# Generated deterministically by seda-macro-lef-normalizer-v1; recipe orfs-ng45-fakeram-metal3-coupledl2-pg-v1.
VERSION 5.8 ;
BUSBITCHARS "[]" ;
DIVIDERCHAR "/" ;

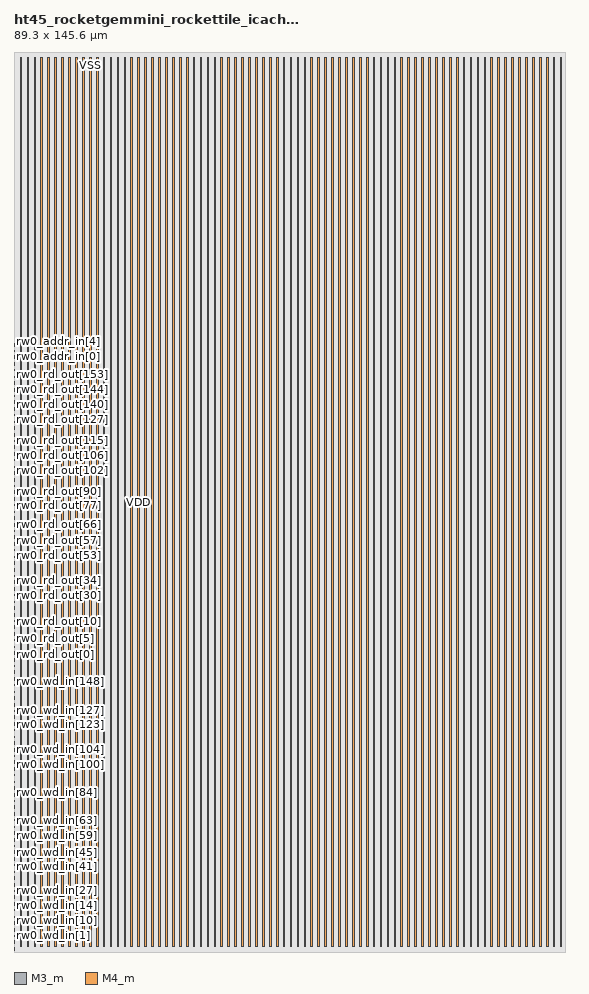
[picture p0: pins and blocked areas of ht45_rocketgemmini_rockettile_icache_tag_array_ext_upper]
MACRO ht45_rocketgemmini_rockettile_icache_tag_array_ext_upper
  FOREIGN ht45_rocketgemmini_rockettile_icache_tag_array_ext_upper 0 0 ;
  CLASS BLOCK ;
  ORIGIN 0 0 ;
  SIZE 89.3 BY 145.6 ;
  SYMMETRY X Y R90 ;
  PIN rw0_wmask_in[0]
    DIRECTION INPUT ;
    USE SIGNAL ;
    SHAPE ABUTMENT ;
    PORT
      LAYER M3_m ;
      RECT 0 0.035 0.07 0.105 ;
    END
  END rw0_wmask_in[0]
  PIN rw0_wmask_in[1]
    DIRECTION INPUT ;
    USE SIGNAL ;
    SHAPE ABUTMENT ;
    PORT
      LAYER M3_m ;
      RECT 0 0.315 0.07 0.385 ;
    END
  END rw0_wmask_in[1]
  PIN rw0_wmask_in[2]
    DIRECTION INPUT ;
    USE SIGNAL ;
    SHAPE ABUTMENT ;
    PORT
      LAYER M3_m ;
      RECT 0 0.595 0.07 0.665 ;
    END
  END rw0_wmask_in[2]
  PIN rw0_wmask_in[3]
    DIRECTION INPUT ;
    USE SIGNAL ;
    SHAPE ABUTMENT ;
    PORT
      LAYER M3_m ;
      RECT 0 0.875 0.07 0.945 ;
    END
  END rw0_wmask_in[3]
  PIN rw0_wmask_in[4]
    DIRECTION INPUT ;
    USE SIGNAL ;
    SHAPE ABUTMENT ;
    PORT
      LAYER M3_m ;
      RECT 0 1.155 0.07 1.225 ;
    END
  END rw0_wmask_in[4]
  PIN rw0_wmask_in[5]
    DIRECTION INPUT ;
    USE SIGNAL ;
    SHAPE ABUTMENT ;
    PORT
      LAYER M3_m ;
      RECT 0 1.435 0.07 1.505 ;
    END
  END rw0_wmask_in[5]
  PIN rw0_wmask_in[6]
    DIRECTION INPUT ;
    USE SIGNAL ;
    SHAPE ABUTMENT ;
    PORT
      LAYER M3_m ;
      RECT 0 1.715 0.07 1.785 ;
    END
  END rw0_wmask_in[6]
  PIN rw0_wmask_in[7]
    DIRECTION INPUT ;
    USE SIGNAL ;
    SHAPE ABUTMENT ;
    PORT
      LAYER M3_m ;
      RECT 0 1.995 0.07 2.065 ;
    END
  END rw0_wmask_in[7]
  PIN rw0_wd_in[0]
    DIRECTION INPUT ;
    USE SIGNAL ;
    SHAPE ABUTMENT ;
    PORT
      LAYER M3_m ;
      RECT 0 2.275 0.07 2.345 ;
    END
  END rw0_wd_in[0]
  PIN rw0_wd_in[1]
    DIRECTION INPUT ;
    USE SIGNAL ;
    SHAPE ABUTMENT ;
    PORT
      LAYER M3_m ;
      RECT 0 2.555 0.07 2.625 ;
    END
  END rw0_wd_in[1]
  PIN rw0_wd_in[2]
    DIRECTION INPUT ;
    USE SIGNAL ;
    SHAPE ABUTMENT ;
    PORT
      LAYER M3_m ;
      RECT 0 2.835 0.07 2.905 ;
    END
  END rw0_wd_in[2]
  PIN rw0_wd_in[3]
    DIRECTION INPUT ;
    USE SIGNAL ;
    SHAPE ABUTMENT ;
    PORT
      LAYER M3_m ;
      RECT 0 3.115 0.07 3.185 ;
    END
  END rw0_wd_in[3]
  PIN rw0_wd_in[4]
    DIRECTION INPUT ;
    USE SIGNAL ;
    SHAPE ABUTMENT ;
    PORT
      LAYER M3_m ;
      RECT 0 3.395 0.07 3.465 ;
    END
  END rw0_wd_in[4]
  PIN rw0_wd_in[5]
    DIRECTION INPUT ;
    USE SIGNAL ;
    SHAPE ABUTMENT ;
    PORT
      LAYER M3_m ;
      RECT 0 3.675 0.07 3.745 ;
    END
  END rw0_wd_in[5]
  PIN rw0_wd_in[6]
    DIRECTION INPUT ;
    USE SIGNAL ;
    SHAPE ABUTMENT ;
    PORT
      LAYER M3_m ;
      RECT 0 3.955 0.07 4.025 ;
    END
  END rw0_wd_in[6]
  PIN rw0_wd_in[7]
    DIRECTION INPUT ;
    USE SIGNAL ;
    SHAPE ABUTMENT ;
    PORT
      LAYER M3_m ;
      RECT 0 4.235 0.07 4.305 ;
    END
  END rw0_wd_in[7]
  PIN rw0_wd_in[8]
    DIRECTION INPUT ;
    USE SIGNAL ;
    SHAPE ABUTMENT ;
    PORT
      LAYER M3_m ;
      RECT 0 4.515 0.07 4.585 ;
    END
  END rw0_wd_in[8]
  PIN rw0_wd_in[9]
    DIRECTION INPUT ;
    USE SIGNAL ;
    SHAPE ABUTMENT ;
    PORT
      LAYER M3_m ;
      RECT 0 4.795 0.07 4.865 ;
    END
  END rw0_wd_in[9]
  PIN rw0_wd_in[10]
    DIRECTION INPUT ;
    USE SIGNAL ;
    SHAPE ABUTMENT ;
    PORT
      LAYER M3_m ;
      RECT 0 5.075 0.07 5.145 ;
    END
  END rw0_wd_in[10]
  PIN rw0_wd_in[11]
    DIRECTION INPUT ;
    USE SIGNAL ;
    SHAPE ABUTMENT ;
    PORT
      LAYER M3_m ;
      RECT 0 5.355 0.07 5.425 ;
    END
  END rw0_wd_in[11]
  PIN rw0_wd_in[12]
    DIRECTION INPUT ;
    USE SIGNAL ;
    SHAPE ABUTMENT ;
    PORT
      LAYER M3_m ;
      RECT 0 5.635 0.07 5.705 ;
    END
  END rw0_wd_in[12]
  PIN rw0_wd_in[13]
    DIRECTION INPUT ;
    USE SIGNAL ;
    SHAPE ABUTMENT ;
    PORT
      LAYER M3_m ;
      RECT 0 5.915 0.07 5.985 ;
    END
  END rw0_wd_in[13]
  PIN rw0_wd_in[14]
    DIRECTION INPUT ;
    USE SIGNAL ;
    SHAPE ABUTMENT ;
    PORT
      LAYER M3_m ;
      RECT 0 6.195 0.07 6.265 ;
    END
  END rw0_wd_in[14]
  PIN rw0_wd_in[15]
    DIRECTION INPUT ;
    USE SIGNAL ;
    SHAPE ABUTMENT ;
    PORT
      LAYER M3_m ;
      RECT 0 6.475 0.07 6.545 ;
    END
  END rw0_wd_in[15]
  PIN rw0_wd_in[16]
    DIRECTION INPUT ;
    USE SIGNAL ;
    SHAPE ABUTMENT ;
    PORT
      LAYER M3_m ;
      RECT 0 6.755 0.07 6.825 ;
    END
  END rw0_wd_in[16]
  PIN rw0_wd_in[17]
    DIRECTION INPUT ;
    USE SIGNAL ;
    SHAPE ABUTMENT ;
    PORT
      LAYER M3_m ;
      RECT 0 7.035 0.07 7.105 ;
    END
  END rw0_wd_in[17]
  PIN rw0_wd_in[18]
    DIRECTION INPUT ;
    USE SIGNAL ;
    SHAPE ABUTMENT ;
    PORT
      LAYER M3_m ;
      RECT 0 7.315 0.07 7.385 ;
    END
  END rw0_wd_in[18]
  PIN rw0_wd_in[19]
    DIRECTION INPUT ;
    USE SIGNAL ;
    SHAPE ABUTMENT ;
    PORT
      LAYER M3_m ;
      RECT 0 7.595 0.07 7.665 ;
    END
  END rw0_wd_in[19]
  PIN rw0_wd_in[20]
    DIRECTION INPUT ;
    USE SIGNAL ;
    SHAPE ABUTMENT ;
    PORT
      LAYER M3_m ;
      RECT 0 7.875 0.07 7.945 ;
    END
  END rw0_wd_in[20]
  PIN rw0_wd_in[21]
    DIRECTION INPUT ;
    USE SIGNAL ;
    SHAPE ABUTMENT ;
    PORT
      LAYER M3_m ;
      RECT 0 8.155 0.07 8.225 ;
    END
  END rw0_wd_in[21]
  PIN rw0_wd_in[22]
    DIRECTION INPUT ;
    USE SIGNAL ;
    SHAPE ABUTMENT ;
    PORT
      LAYER M3_m ;
      RECT 0 8.435 0.07 8.505 ;
    END
  END rw0_wd_in[22]
  PIN rw0_wd_in[23]
    DIRECTION INPUT ;
    USE SIGNAL ;
    SHAPE ABUTMENT ;
    PORT
      LAYER M3_m ;
      RECT 0 8.715 0.07 8.785 ;
    END
  END rw0_wd_in[23]
  PIN rw0_wd_in[24]
    DIRECTION INPUT ;
    USE SIGNAL ;
    SHAPE ABUTMENT ;
    PORT
      LAYER M3_m ;
      RECT 0 8.995 0.07 9.065 ;
    END
  END rw0_wd_in[24]
  PIN rw0_wd_in[25]
    DIRECTION INPUT ;
    USE SIGNAL ;
    SHAPE ABUTMENT ;
    PORT
      LAYER M3_m ;
      RECT 0 9.275 0.07 9.345 ;
    END
  END rw0_wd_in[25]
  PIN rw0_wd_in[26]
    DIRECTION INPUT ;
    USE SIGNAL ;
    SHAPE ABUTMENT ;
    PORT
      LAYER M3_m ;
      RECT 0 9.555 0.07 9.625 ;
    END
  END rw0_wd_in[26]
  PIN rw0_wd_in[27]
    DIRECTION INPUT ;
    USE SIGNAL ;
    SHAPE ABUTMENT ;
    PORT
      LAYER M3_m ;
      RECT 0 9.835 0.07 9.905 ;
    END
  END rw0_wd_in[27]
  PIN rw0_wd_in[28]
    DIRECTION INPUT ;
    USE SIGNAL ;
    SHAPE ABUTMENT ;
    PORT
      LAYER M3_m ;
      RECT 0 10.115 0.07 10.185 ;
    END
  END rw0_wd_in[28]
  PIN rw0_wd_in[29]
    DIRECTION INPUT ;
    USE SIGNAL ;
    SHAPE ABUTMENT ;
    PORT
      LAYER M3_m ;
      RECT 0 10.395 0.07 10.465 ;
    END
  END rw0_wd_in[29]
  PIN rw0_wd_in[30]
    DIRECTION INPUT ;
    USE SIGNAL ;
    SHAPE ABUTMENT ;
    PORT
      LAYER M3_m ;
      RECT 0 10.675 0.07 10.745 ;
    END
  END rw0_wd_in[30]
  PIN rw0_wd_in[31]
    DIRECTION INPUT ;
    USE SIGNAL ;
    SHAPE ABUTMENT ;
    PORT
      LAYER M3_m ;
      RECT 0 10.955 0.07 11.025 ;
    END
  END rw0_wd_in[31]
  PIN rw0_wd_in[32]
    DIRECTION INPUT ;
    USE SIGNAL ;
    SHAPE ABUTMENT ;
    PORT
      LAYER M3_m ;
      RECT 0 11.235 0.07 11.305 ;
    END
  END rw0_wd_in[32]
  PIN rw0_wd_in[33]
    DIRECTION INPUT ;
    USE SIGNAL ;
    SHAPE ABUTMENT ;
    PORT
      LAYER M3_m ;
      RECT 0 11.515 0.07 11.585 ;
    END
  END rw0_wd_in[33]
  PIN rw0_wd_in[34]
    DIRECTION INPUT ;
    USE SIGNAL ;
    SHAPE ABUTMENT ;
    PORT
      LAYER M3_m ;
      RECT 0 11.795 0.07 11.865 ;
    END
  END rw0_wd_in[34]
  PIN rw0_wd_in[35]
    DIRECTION INPUT ;
    USE SIGNAL ;
    SHAPE ABUTMENT ;
    PORT
      LAYER M3_m ;
      RECT 0 12.075 0.07 12.145 ;
    END
  END rw0_wd_in[35]
  PIN rw0_wd_in[36]
    DIRECTION INPUT ;
    USE SIGNAL ;
    SHAPE ABUTMENT ;
    PORT
      LAYER M3_m ;
      RECT 0 12.355 0.07 12.425 ;
    END
  END rw0_wd_in[36]
  PIN rw0_wd_in[37]
    DIRECTION INPUT ;
    USE SIGNAL ;
    SHAPE ABUTMENT ;
    PORT
      LAYER M3_m ;
      RECT 0 12.635 0.07 12.705 ;
    END
  END rw0_wd_in[37]
  PIN rw0_wd_in[38]
    DIRECTION INPUT ;
    USE SIGNAL ;
    SHAPE ABUTMENT ;
    PORT
      LAYER M3_m ;
      RECT 0 12.915 0.07 12.985 ;
    END
  END rw0_wd_in[38]
  PIN rw0_wd_in[39]
    DIRECTION INPUT ;
    USE SIGNAL ;
    SHAPE ABUTMENT ;
    PORT
      LAYER M3_m ;
      RECT 0 13.195 0.07 13.265 ;
    END
  END rw0_wd_in[39]
  PIN rw0_wd_in[40]
    DIRECTION INPUT ;
    USE SIGNAL ;
    SHAPE ABUTMENT ;
    PORT
      LAYER M3_m ;
      RECT 0 13.475 0.07 13.545 ;
    END
  END rw0_wd_in[40]
  PIN rw0_wd_in[41]
    DIRECTION INPUT ;
    USE SIGNAL ;
    SHAPE ABUTMENT ;
    PORT
      LAYER M3_m ;
      RECT 0 13.755 0.07 13.825 ;
    END
  END rw0_wd_in[41]
  PIN rw0_wd_in[42]
    DIRECTION INPUT ;
    USE SIGNAL ;
    SHAPE ABUTMENT ;
    PORT
      LAYER M3_m ;
      RECT 0 14.035 0.07 14.105 ;
    END
  END rw0_wd_in[42]
  PIN rw0_wd_in[43]
    DIRECTION INPUT ;
    USE SIGNAL ;
    SHAPE ABUTMENT ;
    PORT
      LAYER M3_m ;
      RECT 0 14.315 0.07 14.385 ;
    END
  END rw0_wd_in[43]
  PIN rw0_wd_in[44]
    DIRECTION INPUT ;
    USE SIGNAL ;
    SHAPE ABUTMENT ;
    PORT
      LAYER M3_m ;
      RECT 0 14.595 0.07 14.665 ;
    END
  END rw0_wd_in[44]
  PIN rw0_wd_in[45]
    DIRECTION INPUT ;
    USE SIGNAL ;
    SHAPE ABUTMENT ;
    PORT
      LAYER M3_m ;
      RECT 0 14.875 0.07 14.945 ;
    END
  END rw0_wd_in[45]
  PIN rw0_wd_in[46]
    DIRECTION INPUT ;
    USE SIGNAL ;
    SHAPE ABUTMENT ;
    PORT
      LAYER M3_m ;
      RECT 0 15.155 0.07 15.225 ;
    END
  END rw0_wd_in[46]
  PIN rw0_wd_in[47]
    DIRECTION INPUT ;
    USE SIGNAL ;
    SHAPE ABUTMENT ;
    PORT
      LAYER M3_m ;
      RECT 0 15.435 0.07 15.505 ;
    END
  END rw0_wd_in[47]
  PIN rw0_wd_in[48]
    DIRECTION INPUT ;
    USE SIGNAL ;
    SHAPE ABUTMENT ;
    PORT
      LAYER M3_m ;
      RECT 0 15.715 0.07 15.785 ;
    END
  END rw0_wd_in[48]
  PIN rw0_wd_in[49]
    DIRECTION INPUT ;
    USE SIGNAL ;
    SHAPE ABUTMENT ;
    PORT
      LAYER M3_m ;
      RECT 0 15.995 0.07 16.065 ;
    END
  END rw0_wd_in[49]
  PIN rw0_wd_in[50]
    DIRECTION INPUT ;
    USE SIGNAL ;
    SHAPE ABUTMENT ;
    PORT
      LAYER M3_m ;
      RECT 0 16.275 0.07 16.345 ;
    END
  END rw0_wd_in[50]
  PIN rw0_wd_in[51]
    DIRECTION INPUT ;
    USE SIGNAL ;
    SHAPE ABUTMENT ;
    PORT
      LAYER M3_m ;
      RECT 0 16.555 0.07 16.625 ;
    END
  END rw0_wd_in[51]
  PIN rw0_wd_in[52]
    DIRECTION INPUT ;
    USE SIGNAL ;
    SHAPE ABUTMENT ;
    PORT
      LAYER M3_m ;
      RECT 0 16.835 0.07 16.905 ;
    END
  END rw0_wd_in[52]
  PIN rw0_wd_in[53]
    DIRECTION INPUT ;
    USE SIGNAL ;
    SHAPE ABUTMENT ;
    PORT
      LAYER M3_m ;
      RECT 0 17.115 0.07 17.185 ;
    END
  END rw0_wd_in[53]
  PIN rw0_wd_in[54]
    DIRECTION INPUT ;
    USE SIGNAL ;
    SHAPE ABUTMENT ;
    PORT
      LAYER M3_m ;
      RECT 0 17.395 0.07 17.465 ;
    END
  END rw0_wd_in[54]
  PIN rw0_wd_in[55]
    DIRECTION INPUT ;
    USE SIGNAL ;
    SHAPE ABUTMENT ;
    PORT
      LAYER M3_m ;
      RECT 0 17.675 0.07 17.745 ;
    END
  END rw0_wd_in[55]
  PIN rw0_wd_in[56]
    DIRECTION INPUT ;
    USE SIGNAL ;
    SHAPE ABUTMENT ;
    PORT
      LAYER M3_m ;
      RECT 0 17.955 0.07 18.025 ;
    END
  END rw0_wd_in[56]
  PIN rw0_wd_in[57]
    DIRECTION INPUT ;
    USE SIGNAL ;
    SHAPE ABUTMENT ;
    PORT
      LAYER M3_m ;
      RECT 0 18.235 0.07 18.305 ;
    END
  END rw0_wd_in[57]
  PIN rw0_wd_in[58]
    DIRECTION INPUT ;
    USE SIGNAL ;
    SHAPE ABUTMENT ;
    PORT
      LAYER M3_m ;
      RECT 0 18.515 0.07 18.585 ;
    END
  END rw0_wd_in[58]
  PIN rw0_wd_in[59]
    DIRECTION INPUT ;
    USE SIGNAL ;
    SHAPE ABUTMENT ;
    PORT
      LAYER M3_m ;
      RECT 0 18.795 0.07 18.865 ;
    END
  END rw0_wd_in[59]
  PIN rw0_wd_in[60]
    DIRECTION INPUT ;
    USE SIGNAL ;
    SHAPE ABUTMENT ;
    PORT
      LAYER M3_m ;
      RECT 0 19.075 0.07 19.145 ;
    END
  END rw0_wd_in[60]
  PIN rw0_wd_in[61]
    DIRECTION INPUT ;
    USE SIGNAL ;
    SHAPE ABUTMENT ;
    PORT
      LAYER M3_m ;
      RECT 0 19.355 0.07 19.425 ;
    END
  END rw0_wd_in[61]
  PIN rw0_wd_in[62]
    DIRECTION INPUT ;
    USE SIGNAL ;
    SHAPE ABUTMENT ;
    PORT
      LAYER M3_m ;
      RECT 0 19.635 0.07 19.705 ;
    END
  END rw0_wd_in[62]
  PIN rw0_wd_in[63]
    DIRECTION INPUT ;
    USE SIGNAL ;
    SHAPE ABUTMENT ;
    PORT
      LAYER M3_m ;
      RECT 0 19.915 0.07 19.985 ;
    END
  END rw0_wd_in[63]
  PIN rw0_wd_in[64]
    DIRECTION INPUT ;
    USE SIGNAL ;
    SHAPE ABUTMENT ;
    PORT
      LAYER M3_m ;
      RECT 0 20.195 0.07 20.265 ;
    END
  END rw0_wd_in[64]
  PIN rw0_wd_in[65]
    DIRECTION INPUT ;
    USE SIGNAL ;
    SHAPE ABUTMENT ;
    PORT
      LAYER M3_m ;
      RECT 0 20.475 0.07 20.545 ;
    END
  END rw0_wd_in[65]
  PIN rw0_wd_in[66]
    DIRECTION INPUT ;
    USE SIGNAL ;
    SHAPE ABUTMENT ;
    PORT
      LAYER M3_m ;
      RECT 0 20.755 0.07 20.825 ;
    END
  END rw0_wd_in[66]
  PIN rw0_wd_in[67]
    DIRECTION INPUT ;
    USE SIGNAL ;
    SHAPE ABUTMENT ;
    PORT
      LAYER M3_m ;
      RECT 0 21.035 0.07 21.105 ;
    END
  END rw0_wd_in[67]
  PIN rw0_wd_in[68]
    DIRECTION INPUT ;
    USE SIGNAL ;
    SHAPE ABUTMENT ;
    PORT
      LAYER M3_m ;
      RECT 0 21.315 0.07 21.385 ;
    END
  END rw0_wd_in[68]
  PIN rw0_wd_in[69]
    DIRECTION INPUT ;
    USE SIGNAL ;
    SHAPE ABUTMENT ;
    PORT
      LAYER M3_m ;
      RECT 0 21.595 0.07 21.665 ;
    END
  END rw0_wd_in[69]
  PIN rw0_wd_in[70]
    DIRECTION INPUT ;
    USE SIGNAL ;
    SHAPE ABUTMENT ;
    PORT
      LAYER M3_m ;
      RECT 0 21.875 0.07 21.945 ;
    END
  END rw0_wd_in[70]
  PIN rw0_wd_in[71]
    DIRECTION INPUT ;
    USE SIGNAL ;
    SHAPE ABUTMENT ;
    PORT
      LAYER M3_m ;
      RECT 0 22.155 0.07 22.225 ;
    END
  END rw0_wd_in[71]
  PIN rw0_wd_in[72]
    DIRECTION INPUT ;
    USE SIGNAL ;
    SHAPE ABUTMENT ;
    PORT
      LAYER M3_m ;
      RECT 0 22.435 0.07 22.505 ;
    END
  END rw0_wd_in[72]
  PIN rw0_wd_in[73]
    DIRECTION INPUT ;
    USE SIGNAL ;
    SHAPE ABUTMENT ;
    PORT
      LAYER M3_m ;
      RECT 0 22.715 0.07 22.785 ;
    END
  END rw0_wd_in[73]
  PIN rw0_wd_in[74]
    DIRECTION INPUT ;
    USE SIGNAL ;
    SHAPE ABUTMENT ;
    PORT
      LAYER M3_m ;
      RECT 0 22.995 0.07 23.065 ;
    END
  END rw0_wd_in[74]
  PIN rw0_wd_in[75]
    DIRECTION INPUT ;
    USE SIGNAL ;
    SHAPE ABUTMENT ;
    PORT
      LAYER M3_m ;
      RECT 0 23.275 0.07 23.345 ;
    END
  END rw0_wd_in[75]
  PIN rw0_wd_in[76]
    DIRECTION INPUT ;
    USE SIGNAL ;
    SHAPE ABUTMENT ;
    PORT
      LAYER M3_m ;
      RECT 0 23.555 0.07 23.625 ;
    END
  END rw0_wd_in[76]
  PIN rw0_wd_in[77]
    DIRECTION INPUT ;
    USE SIGNAL ;
    SHAPE ABUTMENT ;
    PORT
      LAYER M3_m ;
      RECT 0 23.835 0.07 23.905 ;
    END
  END rw0_wd_in[77]
  PIN rw0_wd_in[78]
    DIRECTION INPUT ;
    USE SIGNAL ;
    SHAPE ABUTMENT ;
    PORT
      LAYER M3_m ;
      RECT 0 24.115 0.07 24.185 ;
    END
  END rw0_wd_in[78]
  PIN rw0_wd_in[79]
    DIRECTION INPUT ;
    USE SIGNAL ;
    SHAPE ABUTMENT ;
    PORT
      LAYER M3_m ;
      RECT 0 24.395 0.07 24.465 ;
    END
  END rw0_wd_in[79]
  PIN rw0_wd_in[80]
    DIRECTION INPUT ;
    USE SIGNAL ;
    SHAPE ABUTMENT ;
    PORT
      LAYER M3_m ;
      RECT 0 24.675 0.07 24.745 ;
    END
  END rw0_wd_in[80]
  PIN rw0_wd_in[81]
    DIRECTION INPUT ;
    USE SIGNAL ;
    SHAPE ABUTMENT ;
    PORT
      LAYER M3_m ;
      RECT 0 24.955 0.07 25.025 ;
    END
  END rw0_wd_in[81]
  PIN rw0_wd_in[82]
    DIRECTION INPUT ;
    USE SIGNAL ;
    SHAPE ABUTMENT ;
    PORT
      LAYER M3_m ;
      RECT 0 25.235 0.07 25.305 ;
    END
  END rw0_wd_in[82]
  PIN rw0_wd_in[83]
    DIRECTION INPUT ;
    USE SIGNAL ;
    SHAPE ABUTMENT ;
    PORT
      LAYER M3_m ;
      RECT 0 25.515 0.07 25.585 ;
    END
  END rw0_wd_in[83]
  PIN rw0_wd_in[84]
    DIRECTION INPUT ;
    USE SIGNAL ;
    SHAPE ABUTMENT ;
    PORT
      LAYER M3_m ;
      RECT 0 25.795 0.07 25.865 ;
    END
  END rw0_wd_in[84]
  PIN rw0_wd_in[85]
    DIRECTION INPUT ;
    USE SIGNAL ;
    SHAPE ABUTMENT ;
    PORT
      LAYER M3_m ;
      RECT 0 26.075 0.07 26.145 ;
    END
  END rw0_wd_in[85]
  PIN rw0_wd_in[86]
    DIRECTION INPUT ;
    USE SIGNAL ;
    SHAPE ABUTMENT ;
    PORT
      LAYER M3_m ;
      RECT 0 26.355 0.07 26.425 ;
    END
  END rw0_wd_in[86]
  PIN rw0_wd_in[87]
    DIRECTION INPUT ;
    USE SIGNAL ;
    SHAPE ABUTMENT ;
    PORT
      LAYER M3_m ;
      RECT 0 26.635 0.07 26.705 ;
    END
  END rw0_wd_in[87]
  PIN rw0_wd_in[88]
    DIRECTION INPUT ;
    USE SIGNAL ;
    SHAPE ABUTMENT ;
    PORT
      LAYER M3_m ;
      RECT 0 26.915 0.07 26.985 ;
    END
  END rw0_wd_in[88]
  PIN rw0_wd_in[89]
    DIRECTION INPUT ;
    USE SIGNAL ;
    SHAPE ABUTMENT ;
    PORT
      LAYER M3_m ;
      RECT 0 27.195 0.07 27.265 ;
    END
  END rw0_wd_in[89]
  PIN rw0_wd_in[90]
    DIRECTION INPUT ;
    USE SIGNAL ;
    SHAPE ABUTMENT ;
    PORT
      LAYER M3_m ;
      RECT 0 27.475 0.07 27.545 ;
    END
  END rw0_wd_in[90]
  PIN rw0_wd_in[91]
    DIRECTION INPUT ;
    USE SIGNAL ;
    SHAPE ABUTMENT ;
    PORT
      LAYER M3_m ;
      RECT 0 27.755 0.07 27.825 ;
    END
  END rw0_wd_in[91]
  PIN rw0_wd_in[92]
    DIRECTION INPUT ;
    USE SIGNAL ;
    SHAPE ABUTMENT ;
    PORT
      LAYER M3_m ;
      RECT 0 28.035 0.07 28.105 ;
    END
  END rw0_wd_in[92]
  PIN rw0_wd_in[93]
    DIRECTION INPUT ;
    USE SIGNAL ;
    SHAPE ABUTMENT ;
    PORT
      LAYER M3_m ;
      RECT 0 28.315 0.07 28.385 ;
    END
  END rw0_wd_in[93]
  PIN rw0_wd_in[94]
    DIRECTION INPUT ;
    USE SIGNAL ;
    SHAPE ABUTMENT ;
    PORT
      LAYER M3_m ;
      RECT 0 28.595 0.07 28.665 ;
    END
  END rw0_wd_in[94]
  PIN rw0_wd_in[95]
    DIRECTION INPUT ;
    USE SIGNAL ;
    SHAPE ABUTMENT ;
    PORT
      LAYER M3_m ;
      RECT 0 28.875 0.07 28.945 ;
    END
  END rw0_wd_in[95]
  PIN rw0_wd_in[96]
    DIRECTION INPUT ;
    USE SIGNAL ;
    SHAPE ABUTMENT ;
    PORT
      LAYER M3_m ;
      RECT 0 29.155 0.07 29.225 ;
    END
  END rw0_wd_in[96]
  PIN rw0_wd_in[97]
    DIRECTION INPUT ;
    USE SIGNAL ;
    SHAPE ABUTMENT ;
    PORT
      LAYER M3_m ;
      RECT 0 29.435 0.07 29.505 ;
    END
  END rw0_wd_in[97]
  PIN rw0_wd_in[98]
    DIRECTION INPUT ;
    USE SIGNAL ;
    SHAPE ABUTMENT ;
    PORT
      LAYER M3_m ;
      RECT 0 29.715 0.07 29.785 ;
    END
  END rw0_wd_in[98]
  PIN rw0_wd_in[99]
    DIRECTION INPUT ;
    USE SIGNAL ;
    SHAPE ABUTMENT ;
    PORT
      LAYER M3_m ;
      RECT 0 29.995 0.07 30.065 ;
    END
  END rw0_wd_in[99]
  PIN rw0_wd_in[100]
    DIRECTION INPUT ;
    USE SIGNAL ;
    SHAPE ABUTMENT ;
    PORT
      LAYER M3_m ;
      RECT 0 30.275 0.07 30.345 ;
    END
  END rw0_wd_in[100]
  PIN rw0_wd_in[101]
    DIRECTION INPUT ;
    USE SIGNAL ;
    SHAPE ABUTMENT ;
    PORT
      LAYER M3_m ;
      RECT 0 30.555 0.07 30.625 ;
    END
  END rw0_wd_in[101]
  PIN rw0_wd_in[102]
    DIRECTION INPUT ;
    USE SIGNAL ;
    SHAPE ABUTMENT ;
    PORT
      LAYER M3_m ;
      RECT 0 30.835 0.07 30.905 ;
    END
  END rw0_wd_in[102]
  PIN rw0_wd_in[103]
    DIRECTION INPUT ;
    USE SIGNAL ;
    SHAPE ABUTMENT ;
    PORT
      LAYER M3_m ;
      RECT 0 31.115 0.07 31.185 ;
    END
  END rw0_wd_in[103]
  PIN rw0_wd_in[104]
    DIRECTION INPUT ;
    USE SIGNAL ;
    SHAPE ABUTMENT ;
    PORT
      LAYER M3_m ;
      RECT 0 31.395 0.07 31.465 ;
    END
  END rw0_wd_in[104]
  PIN rw0_wd_in[105]
    DIRECTION INPUT ;
    USE SIGNAL ;
    SHAPE ABUTMENT ;
    PORT
      LAYER M3_m ;
      RECT 0 31.675 0.07 31.745 ;
    END
  END rw0_wd_in[105]
  PIN rw0_wd_in[106]
    DIRECTION INPUT ;
    USE SIGNAL ;
    SHAPE ABUTMENT ;
    PORT
      LAYER M3_m ;
      RECT 0 31.955 0.07 32.025 ;
    END
  END rw0_wd_in[106]
  PIN rw0_wd_in[107]
    DIRECTION INPUT ;
    USE SIGNAL ;
    SHAPE ABUTMENT ;
    PORT
      LAYER M3_m ;
      RECT 0 32.235 0.07 32.305 ;
    END
  END rw0_wd_in[107]
  PIN rw0_wd_in[108]
    DIRECTION INPUT ;
    USE SIGNAL ;
    SHAPE ABUTMENT ;
    PORT
      LAYER M3_m ;
      RECT 0 32.515 0.07 32.585 ;
    END
  END rw0_wd_in[108]
  PIN rw0_wd_in[109]
    DIRECTION INPUT ;
    USE SIGNAL ;
    SHAPE ABUTMENT ;
    PORT
      LAYER M3_m ;
      RECT 0 32.795 0.07 32.865 ;
    END
  END rw0_wd_in[109]
  PIN rw0_wd_in[110]
    DIRECTION INPUT ;
    USE SIGNAL ;
    SHAPE ABUTMENT ;
    PORT
      LAYER M3_m ;
      RECT 0 33.075 0.07 33.145 ;
    END
  END rw0_wd_in[110]
  PIN rw0_wd_in[111]
    DIRECTION INPUT ;
    USE SIGNAL ;
    SHAPE ABUTMENT ;
    PORT
      LAYER M3_m ;
      RECT 0 33.355 0.07 33.425 ;
    END
  END rw0_wd_in[111]
  PIN rw0_wd_in[112]
    DIRECTION INPUT ;
    USE SIGNAL ;
    SHAPE ABUTMENT ;
    PORT
      LAYER M3_m ;
      RECT 0 33.635 0.07 33.705 ;
    END
  END rw0_wd_in[112]
  PIN rw0_wd_in[113]
    DIRECTION INPUT ;
    USE SIGNAL ;
    SHAPE ABUTMENT ;
    PORT
      LAYER M3_m ;
      RECT 0 33.915 0.07 33.985 ;
    END
  END rw0_wd_in[113]
  PIN rw0_wd_in[114]
    DIRECTION INPUT ;
    USE SIGNAL ;
    SHAPE ABUTMENT ;
    PORT
      LAYER M3_m ;
      RECT 0 34.195 0.07 34.265 ;
    END
  END rw0_wd_in[114]
  PIN rw0_wd_in[115]
    DIRECTION INPUT ;
    USE SIGNAL ;
    SHAPE ABUTMENT ;
    PORT
      LAYER M3_m ;
      RECT 0 34.475 0.07 34.545 ;
    END
  END rw0_wd_in[115]
  PIN rw0_wd_in[116]
    DIRECTION INPUT ;
    USE SIGNAL ;
    SHAPE ABUTMENT ;
    PORT
      LAYER M3_m ;
      RECT 0 34.755 0.07 34.825 ;
    END
  END rw0_wd_in[116]
  PIN rw0_wd_in[117]
    DIRECTION INPUT ;
    USE SIGNAL ;
    SHAPE ABUTMENT ;
    PORT
      LAYER M3_m ;
      RECT 0 35.035 0.07 35.105 ;
    END
  END rw0_wd_in[117]
  PIN rw0_wd_in[118]
    DIRECTION INPUT ;
    USE SIGNAL ;
    SHAPE ABUTMENT ;
    PORT
      LAYER M3_m ;
      RECT 0 35.315 0.07 35.385 ;
    END
  END rw0_wd_in[118]
  PIN rw0_wd_in[119]
    DIRECTION INPUT ;
    USE SIGNAL ;
    SHAPE ABUTMENT ;
    PORT
      LAYER M3_m ;
      RECT 0 35.595 0.07 35.665 ;
    END
  END rw0_wd_in[119]
  PIN rw0_wd_in[120]
    DIRECTION INPUT ;
    USE SIGNAL ;
    SHAPE ABUTMENT ;
    PORT
      LAYER M3_m ;
      RECT 0 35.875 0.07 35.945 ;
    END
  END rw0_wd_in[120]
  PIN rw0_wd_in[121]
    DIRECTION INPUT ;
    USE SIGNAL ;
    SHAPE ABUTMENT ;
    PORT
      LAYER M3_m ;
      RECT 0 36.155 0.07 36.225 ;
    END
  END rw0_wd_in[121]
  PIN rw0_wd_in[122]
    DIRECTION INPUT ;
    USE SIGNAL ;
    SHAPE ABUTMENT ;
    PORT
      LAYER M3_m ;
      RECT 0 36.435 0.07 36.505 ;
    END
  END rw0_wd_in[122]
  PIN rw0_wd_in[123]
    DIRECTION INPUT ;
    USE SIGNAL ;
    SHAPE ABUTMENT ;
    PORT
      LAYER M3_m ;
      RECT 0 36.715 0.07 36.785 ;
    END
  END rw0_wd_in[123]
  PIN rw0_wd_in[124]
    DIRECTION INPUT ;
    USE SIGNAL ;
    SHAPE ABUTMENT ;
    PORT
      LAYER M3_m ;
      RECT 0 36.995 0.07 37.065 ;
    END
  END rw0_wd_in[124]
  PIN rw0_wd_in[125]
    DIRECTION INPUT ;
    USE SIGNAL ;
    SHAPE ABUTMENT ;
    PORT
      LAYER M3_m ;
      RECT 0 37.275 0.07 37.345 ;
    END
  END rw0_wd_in[125]
  PIN rw0_wd_in[126]
    DIRECTION INPUT ;
    USE SIGNAL ;
    SHAPE ABUTMENT ;
    PORT
      LAYER M3_m ;
      RECT 0 37.555 0.07 37.625 ;
    END
  END rw0_wd_in[126]
  PIN rw0_wd_in[127]
    DIRECTION INPUT ;
    USE SIGNAL ;
    SHAPE ABUTMENT ;
    PORT
      LAYER M3_m ;
      RECT 0 37.835 0.07 37.905 ;
    END
  END rw0_wd_in[127]
  PIN rw0_wd_in[128]
    DIRECTION INPUT ;
    USE SIGNAL ;
    SHAPE ABUTMENT ;
    PORT
      LAYER M3_m ;
      RECT 0 38.115 0.07 38.185 ;
    END
  END rw0_wd_in[128]
  PIN rw0_wd_in[129]
    DIRECTION INPUT ;
    USE SIGNAL ;
    SHAPE ABUTMENT ;
    PORT
      LAYER M3_m ;
      RECT 0 38.395 0.07 38.465 ;
    END
  END rw0_wd_in[129]
  PIN rw0_wd_in[130]
    DIRECTION INPUT ;
    USE SIGNAL ;
    SHAPE ABUTMENT ;
    PORT
      LAYER M3_m ;
      RECT 0 38.675 0.07 38.745 ;
    END
  END rw0_wd_in[130]
  PIN rw0_wd_in[131]
    DIRECTION INPUT ;
    USE SIGNAL ;
    SHAPE ABUTMENT ;
    PORT
      LAYER M3_m ;
      RECT 0 38.955 0.07 39.025 ;
    END
  END rw0_wd_in[131]
  PIN rw0_wd_in[132]
    DIRECTION INPUT ;
    USE SIGNAL ;
    SHAPE ABUTMENT ;
    PORT
      LAYER M3_m ;
      RECT 0 39.235 0.07 39.305 ;
    END
  END rw0_wd_in[132]
  PIN rw0_wd_in[133]
    DIRECTION INPUT ;
    USE SIGNAL ;
    SHAPE ABUTMENT ;
    PORT
      LAYER M3_m ;
      RECT 0 39.515 0.07 39.585 ;
    END
  END rw0_wd_in[133]
  PIN rw0_wd_in[134]
    DIRECTION INPUT ;
    USE SIGNAL ;
    SHAPE ABUTMENT ;
    PORT
      LAYER M3_m ;
      RECT 0 39.795 0.07 39.865 ;
    END
  END rw0_wd_in[134]
  PIN rw0_wd_in[135]
    DIRECTION INPUT ;
    USE SIGNAL ;
    SHAPE ABUTMENT ;
    PORT
      LAYER M3_m ;
      RECT 0 40.075 0.07 40.145 ;
    END
  END rw0_wd_in[135]
  PIN rw0_wd_in[136]
    DIRECTION INPUT ;
    USE SIGNAL ;
    SHAPE ABUTMENT ;
    PORT
      LAYER M3_m ;
      RECT 0 40.355 0.07 40.425 ;
    END
  END rw0_wd_in[136]
  PIN rw0_wd_in[137]
    DIRECTION INPUT ;
    USE SIGNAL ;
    SHAPE ABUTMENT ;
    PORT
      LAYER M3_m ;
      RECT 0 40.635 0.07 40.705 ;
    END
  END rw0_wd_in[137]
  PIN rw0_wd_in[138]
    DIRECTION INPUT ;
    USE SIGNAL ;
    SHAPE ABUTMENT ;
    PORT
      LAYER M3_m ;
      RECT 0 40.915 0.07 40.985 ;
    END
  END rw0_wd_in[138]
  PIN rw0_wd_in[139]
    DIRECTION INPUT ;
    USE SIGNAL ;
    SHAPE ABUTMENT ;
    PORT
      LAYER M3_m ;
      RECT 0 41.195 0.07 41.265 ;
    END
  END rw0_wd_in[139]
  PIN rw0_wd_in[140]
    DIRECTION INPUT ;
    USE SIGNAL ;
    SHAPE ABUTMENT ;
    PORT
      LAYER M3_m ;
      RECT 0 41.475 0.07 41.545 ;
    END
  END rw0_wd_in[140]
  PIN rw0_wd_in[141]
    DIRECTION INPUT ;
    USE SIGNAL ;
    SHAPE ABUTMENT ;
    PORT
      LAYER M3_m ;
      RECT 0 41.755 0.07 41.825 ;
    END
  END rw0_wd_in[141]
  PIN rw0_wd_in[142]
    DIRECTION INPUT ;
    USE SIGNAL ;
    SHAPE ABUTMENT ;
    PORT
      LAYER M3_m ;
      RECT 0 42.035 0.07 42.105 ;
    END
  END rw0_wd_in[142]
  PIN rw0_wd_in[143]
    DIRECTION INPUT ;
    USE SIGNAL ;
    SHAPE ABUTMENT ;
    PORT
      LAYER M3_m ;
      RECT 0 42.315 0.07 42.385 ;
    END
  END rw0_wd_in[143]
  PIN rw0_wd_in[144]
    DIRECTION INPUT ;
    USE SIGNAL ;
    SHAPE ABUTMENT ;
    PORT
      LAYER M3_m ;
      RECT 0 42.595 0.07 42.665 ;
    END
  END rw0_wd_in[144]
  PIN rw0_wd_in[145]
    DIRECTION INPUT ;
    USE SIGNAL ;
    SHAPE ABUTMENT ;
    PORT
      LAYER M3_m ;
      RECT 0 42.875 0.07 42.945 ;
    END
  END rw0_wd_in[145]
  PIN rw0_wd_in[146]
    DIRECTION INPUT ;
    USE SIGNAL ;
    SHAPE ABUTMENT ;
    PORT
      LAYER M3_m ;
      RECT 0 43.155 0.07 43.225 ;
    END
  END rw0_wd_in[146]
  PIN rw0_wd_in[147]
    DIRECTION INPUT ;
    USE SIGNAL ;
    SHAPE ABUTMENT ;
    PORT
      LAYER M3_m ;
      RECT 0 43.435 0.07 43.505 ;
    END
  END rw0_wd_in[147]
  PIN rw0_wd_in[148]
    DIRECTION INPUT ;
    USE SIGNAL ;
    SHAPE ABUTMENT ;
    PORT
      LAYER M3_m ;
      RECT 0 43.715 0.07 43.785 ;
    END
  END rw0_wd_in[148]
  PIN rw0_wd_in[149]
    DIRECTION INPUT ;
    USE SIGNAL ;
    SHAPE ABUTMENT ;
    PORT
      LAYER M3_m ;
      RECT 0 43.995 0.07 44.065 ;
    END
  END rw0_wd_in[149]
  PIN rw0_wd_in[150]
    DIRECTION INPUT ;
    USE SIGNAL ;
    SHAPE ABUTMENT ;
    PORT
      LAYER M3_m ;
      RECT 0 44.275 0.07 44.345 ;
    END
  END rw0_wd_in[150]
  PIN rw0_wd_in[151]
    DIRECTION INPUT ;
    USE SIGNAL ;
    SHAPE ABUTMENT ;
    PORT
      LAYER M3_m ;
      RECT 0 44.555 0.07 44.625 ;
    END
  END rw0_wd_in[151]
  PIN rw0_wd_in[152]
    DIRECTION INPUT ;
    USE SIGNAL ;
    SHAPE ABUTMENT ;
    PORT
      LAYER M3_m ;
      RECT 0 44.835 0.07 44.905 ;
    END
  END rw0_wd_in[152]
  PIN rw0_wd_in[153]
    DIRECTION INPUT ;
    USE SIGNAL ;
    SHAPE ABUTMENT ;
    PORT
      LAYER M3_m ;
      RECT 0 45.115 0.07 45.185 ;
    END
  END rw0_wd_in[153]
  PIN rw0_wd_in[154]
    DIRECTION INPUT ;
    USE SIGNAL ;
    SHAPE ABUTMENT ;
    PORT
      LAYER M3_m ;
      RECT 0 45.395 0.07 45.465 ;
    END
  END rw0_wd_in[154]
  PIN rw0_wd_in[155]
    DIRECTION INPUT ;
    USE SIGNAL ;
    SHAPE ABUTMENT ;
    PORT
      LAYER M3_m ;
      RECT 0 45.675 0.07 45.745 ;
    END
  END rw0_wd_in[155]
  PIN rw0_wd_in[156]
    DIRECTION INPUT ;
    USE SIGNAL ;
    SHAPE ABUTMENT ;
    PORT
      LAYER M3_m ;
      RECT 0 45.955 0.07 46.025 ;
    END
  END rw0_wd_in[156]
  PIN rw0_wd_in[157]
    DIRECTION INPUT ;
    USE SIGNAL ;
    SHAPE ABUTMENT ;
    PORT
      LAYER M3_m ;
      RECT 0 46.235 0.07 46.305 ;
    END
  END rw0_wd_in[157]
  PIN rw0_wd_in[158]
    DIRECTION INPUT ;
    USE SIGNAL ;
    SHAPE ABUTMENT ;
    PORT
      LAYER M3_m ;
      RECT 0 46.515 0.07 46.585 ;
    END
  END rw0_wd_in[158]
  PIN rw0_wd_in[159]
    DIRECTION INPUT ;
    USE SIGNAL ;
    SHAPE ABUTMENT ;
    PORT
      LAYER M3_m ;
      RECT 0 46.795 0.07 46.865 ;
    END
  END rw0_wd_in[159]
  PIN rw0_wd_in[160]
    DIRECTION INPUT ;
    USE SIGNAL ;
    SHAPE ABUTMENT ;
    PORT
      LAYER M3_m ;
      RECT 0 47.075 0.07 47.145 ;
    END
  END rw0_wd_in[160]
  PIN rw0_wd_in[161]
    DIRECTION INPUT ;
    USE SIGNAL ;
    SHAPE ABUTMENT ;
    PORT
      LAYER M3_m ;
      RECT 0 47.355 0.07 47.425 ;
    END
  END rw0_wd_in[161]
  PIN rw0_wd_in[162]
    DIRECTION INPUT ;
    USE SIGNAL ;
    SHAPE ABUTMENT ;
    PORT
      LAYER M3_m ;
      RECT 0 47.635 0.07 47.705 ;
    END
  END rw0_wd_in[162]
  PIN rw0_wd_in[163]
    DIRECTION INPUT ;
    USE SIGNAL ;
    SHAPE ABUTMENT ;
    PORT
      LAYER M3_m ;
      RECT 0 47.915 0.07 47.985 ;
    END
  END rw0_wd_in[163]
  PIN rw0_wd_in[164]
    DIRECTION INPUT ;
    USE SIGNAL ;
    SHAPE ABUTMENT ;
    PORT
      LAYER M3_m ;
      RECT 0 48.195 0.07 48.265 ;
    END
  END rw0_wd_in[164]
  PIN rw0_wd_in[165]
    DIRECTION INPUT ;
    USE SIGNAL ;
    SHAPE ABUTMENT ;
    PORT
      LAYER M3_m ;
      RECT 0 48.475 0.07 48.545 ;
    END
  END rw0_wd_in[165]
  PIN rw0_wd_in[166]
    DIRECTION INPUT ;
    USE SIGNAL ;
    SHAPE ABUTMENT ;
    PORT
      LAYER M3_m ;
      RECT 0 48.755 0.07 48.825 ;
    END
  END rw0_wd_in[166]
  PIN rw0_wd_in[167]
    DIRECTION INPUT ;
    USE SIGNAL ;
    SHAPE ABUTMENT ;
    PORT
      LAYER M3_m ;
      RECT 0 49.035 0.07 49.105 ;
    END
  END rw0_wd_in[167]
  PIN rw0_rd_out[0]
    DIRECTION OUTPUT ;
    USE SIGNAL ;
    SHAPE ABUTMENT ;
    PORT
      LAYER M3_m ;
      RECT 0 49.315 0.07 49.385 ;
    END
  END rw0_rd_out[0]
  PIN rw0_rd_out[1]
    DIRECTION OUTPUT ;
    USE SIGNAL ;
    SHAPE ABUTMENT ;
    PORT
      LAYER M3_m ;
      RECT 0 49.595 0.07 49.665 ;
    END
  END rw0_rd_out[1]
  PIN rw0_rd_out[2]
    DIRECTION OUTPUT ;
    USE SIGNAL ;
    SHAPE ABUTMENT ;
    PORT
      LAYER M3_m ;
      RECT 0 49.875 0.07 49.945 ;
    END
  END rw0_rd_out[2]
  PIN rw0_rd_out[3]
    DIRECTION OUTPUT ;
    USE SIGNAL ;
    SHAPE ABUTMENT ;
    PORT
      LAYER M3_m ;
      RECT 0 50.155 0.07 50.225 ;
    END
  END rw0_rd_out[3]
  PIN rw0_rd_out[4]
    DIRECTION OUTPUT ;
    USE SIGNAL ;
    SHAPE ABUTMENT ;
    PORT
      LAYER M3_m ;
      RECT 0 50.435 0.07 50.505 ;
    END
  END rw0_rd_out[4]
  PIN rw0_rd_out[5]
    DIRECTION OUTPUT ;
    USE SIGNAL ;
    SHAPE ABUTMENT ;
    PORT
      LAYER M3_m ;
      RECT 0 50.715 0.07 50.785 ;
    END
  END rw0_rd_out[5]
  PIN rw0_rd_out[6]
    DIRECTION OUTPUT ;
    USE SIGNAL ;
    SHAPE ABUTMENT ;
    PORT
      LAYER M3_m ;
      RECT 0 50.995 0.07 51.065 ;
    END
  END rw0_rd_out[6]
  PIN rw0_rd_out[7]
    DIRECTION OUTPUT ;
    USE SIGNAL ;
    SHAPE ABUTMENT ;
    PORT
      LAYER M3_m ;
      RECT 0 51.275 0.07 51.345 ;
    END
  END rw0_rd_out[7]
  PIN rw0_rd_out[8]
    DIRECTION OUTPUT ;
    USE SIGNAL ;
    SHAPE ABUTMENT ;
    PORT
      LAYER M3_m ;
      RECT 0 51.555 0.07 51.625 ;
    END
  END rw0_rd_out[8]
  PIN rw0_rd_out[9]
    DIRECTION OUTPUT ;
    USE SIGNAL ;
    SHAPE ABUTMENT ;
    PORT
      LAYER M3_m ;
      RECT 0 51.835 0.07 51.905 ;
    END
  END rw0_rd_out[9]
  PIN rw0_rd_out[10]
    DIRECTION OUTPUT ;
    USE SIGNAL ;
    SHAPE ABUTMENT ;
    PORT
      LAYER M3_m ;
      RECT 0 52.115 0.07 52.185 ;
    END
  END rw0_rd_out[10]
  PIN rw0_rd_out[11]
    DIRECTION OUTPUT ;
    USE SIGNAL ;
    SHAPE ABUTMENT ;
    PORT
      LAYER M3_m ;
      RECT 0 52.395 0.07 52.465 ;
    END
  END rw0_rd_out[11]
  PIN rw0_rd_out[12]
    DIRECTION OUTPUT ;
    USE SIGNAL ;
    SHAPE ABUTMENT ;
    PORT
      LAYER M3_m ;
      RECT 0 52.675 0.07 52.745 ;
    END
  END rw0_rd_out[12]
  PIN rw0_rd_out[13]
    DIRECTION OUTPUT ;
    USE SIGNAL ;
    SHAPE ABUTMENT ;
    PORT
      LAYER M3_m ;
      RECT 0 52.955 0.07 53.025 ;
    END
  END rw0_rd_out[13]
  PIN rw0_rd_out[14]
    DIRECTION OUTPUT ;
    USE SIGNAL ;
    SHAPE ABUTMENT ;
    PORT
      LAYER M3_m ;
      RECT 0 53.235 0.07 53.305 ;
    END
  END rw0_rd_out[14]
  PIN rw0_rd_out[15]
    DIRECTION OUTPUT ;
    USE SIGNAL ;
    SHAPE ABUTMENT ;
    PORT
      LAYER M3_m ;
      RECT 0 53.515 0.07 53.585 ;
    END
  END rw0_rd_out[15]
  PIN rw0_rd_out[16]
    DIRECTION OUTPUT ;
    USE SIGNAL ;
    SHAPE ABUTMENT ;
    PORT
      LAYER M3_m ;
      RECT 0 53.795 0.07 53.865 ;
    END
  END rw0_rd_out[16]
  PIN rw0_rd_out[17]
    DIRECTION OUTPUT ;
    USE SIGNAL ;
    SHAPE ABUTMENT ;
    PORT
      LAYER M3_m ;
      RECT 0 54.075 0.07 54.145 ;
    END
  END rw0_rd_out[17]
  PIN rw0_rd_out[18]
    DIRECTION OUTPUT ;
    USE SIGNAL ;
    SHAPE ABUTMENT ;
    PORT
      LAYER M3_m ;
      RECT 0 54.355 0.07 54.425 ;
    END
  END rw0_rd_out[18]
  PIN rw0_rd_out[19]
    DIRECTION OUTPUT ;
    USE SIGNAL ;
    SHAPE ABUTMENT ;
    PORT
      LAYER M3_m ;
      RECT 0 54.635 0.07 54.705 ;
    END
  END rw0_rd_out[19]
  PIN rw0_rd_out[20]
    DIRECTION OUTPUT ;
    USE SIGNAL ;
    SHAPE ABUTMENT ;
    PORT
      LAYER M3_m ;
      RECT 0 54.915 0.07 54.985 ;
    END
  END rw0_rd_out[20]
  PIN rw0_rd_out[21]
    DIRECTION OUTPUT ;
    USE SIGNAL ;
    SHAPE ABUTMENT ;
    PORT
      LAYER M3_m ;
      RECT 0 55.195 0.07 55.265 ;
    END
  END rw0_rd_out[21]
  PIN rw0_rd_out[22]
    DIRECTION OUTPUT ;
    USE SIGNAL ;
    SHAPE ABUTMENT ;
    PORT
      LAYER M3_m ;
      RECT 0 55.475 0.07 55.545 ;
    END
  END rw0_rd_out[22]
  PIN rw0_rd_out[23]
    DIRECTION OUTPUT ;
    USE SIGNAL ;
    SHAPE ABUTMENT ;
    PORT
      LAYER M3_m ;
      RECT 0 55.755 0.07 55.825 ;
    END
  END rw0_rd_out[23]
  PIN rw0_rd_out[24]
    DIRECTION OUTPUT ;
    USE SIGNAL ;
    SHAPE ABUTMENT ;
    PORT
      LAYER M3_m ;
      RECT 0 56.035 0.07 56.105 ;
    END
  END rw0_rd_out[24]
  PIN rw0_rd_out[25]
    DIRECTION OUTPUT ;
    USE SIGNAL ;
    SHAPE ABUTMENT ;
    PORT
      LAYER M3_m ;
      RECT 0 56.315 0.07 56.385 ;
    END
  END rw0_rd_out[25]
  PIN rw0_rd_out[26]
    DIRECTION OUTPUT ;
    USE SIGNAL ;
    SHAPE ABUTMENT ;
    PORT
      LAYER M3_m ;
      RECT 0 56.595 0.07 56.665 ;
    END
  END rw0_rd_out[26]
  PIN rw0_rd_out[27]
    DIRECTION OUTPUT ;
    USE SIGNAL ;
    SHAPE ABUTMENT ;
    PORT
      LAYER M3_m ;
      RECT 0 56.875 0.07 56.945 ;
    END
  END rw0_rd_out[27]
  PIN rw0_rd_out[28]
    DIRECTION OUTPUT ;
    USE SIGNAL ;
    SHAPE ABUTMENT ;
    PORT
      LAYER M3_m ;
      RECT 0 57.155 0.07 57.225 ;
    END
  END rw0_rd_out[28]
  PIN rw0_rd_out[29]
    DIRECTION OUTPUT ;
    USE SIGNAL ;
    SHAPE ABUTMENT ;
    PORT
      LAYER M3_m ;
      RECT 0 57.435 0.07 57.505 ;
    END
  END rw0_rd_out[29]
  PIN rw0_rd_out[30]
    DIRECTION OUTPUT ;
    USE SIGNAL ;
    SHAPE ABUTMENT ;
    PORT
      LAYER M3_m ;
      RECT 0 57.715 0.07 57.785 ;
    END
  END rw0_rd_out[30]
  PIN rw0_rd_out[31]
    DIRECTION OUTPUT ;
    USE SIGNAL ;
    SHAPE ABUTMENT ;
    PORT
      LAYER M3_m ;
      RECT 0 57.995 0.07 58.065 ;
    END
  END rw0_rd_out[31]
  PIN rw0_rd_out[32]
    DIRECTION OUTPUT ;
    USE SIGNAL ;
    SHAPE ABUTMENT ;
    PORT
      LAYER M3_m ;
      RECT 0 58.275 0.07 58.345 ;
    END
  END rw0_rd_out[32]
  PIN rw0_rd_out[33]
    DIRECTION OUTPUT ;
    USE SIGNAL ;
    SHAPE ABUTMENT ;
    PORT
      LAYER M3_m ;
      RECT 0 58.555 0.07 58.625 ;
    END
  END rw0_rd_out[33]
  PIN rw0_rd_out[34]
    DIRECTION OUTPUT ;
    USE SIGNAL ;
    SHAPE ABUTMENT ;
    PORT
      LAYER M3_m ;
      RECT 0 58.835 0.07 58.905 ;
    END
  END rw0_rd_out[34]
  PIN rw0_rd_out[35]
    DIRECTION OUTPUT ;
    USE SIGNAL ;
    SHAPE ABUTMENT ;
    PORT
      LAYER M3_m ;
      RECT 0 59.115 0.07 59.185 ;
    END
  END rw0_rd_out[35]
  PIN rw0_rd_out[36]
    DIRECTION OUTPUT ;
    USE SIGNAL ;
    SHAPE ABUTMENT ;
    PORT
      LAYER M3_m ;
      RECT 0 59.395 0.07 59.465 ;
    END
  END rw0_rd_out[36]
  PIN rw0_rd_out[37]
    DIRECTION OUTPUT ;
    USE SIGNAL ;
    SHAPE ABUTMENT ;
    PORT
      LAYER M3_m ;
      RECT 0 59.675 0.07 59.745 ;
    END
  END rw0_rd_out[37]
  PIN rw0_rd_out[38]
    DIRECTION OUTPUT ;
    USE SIGNAL ;
    SHAPE ABUTMENT ;
    PORT
      LAYER M3_m ;
      RECT 0 59.955 0.07 60.025 ;
    END
  END rw0_rd_out[38]
  PIN rw0_rd_out[39]
    DIRECTION OUTPUT ;
    USE SIGNAL ;
    SHAPE ABUTMENT ;
    PORT
      LAYER M3_m ;
      RECT 0 60.235 0.07 60.305 ;
    END
  END rw0_rd_out[39]
  PIN rw0_rd_out[40]
    DIRECTION OUTPUT ;
    USE SIGNAL ;
    SHAPE ABUTMENT ;
    PORT
      LAYER M3_m ;
      RECT 0 60.515 0.07 60.585 ;
    END
  END rw0_rd_out[40]
  PIN rw0_rd_out[41]
    DIRECTION OUTPUT ;
    USE SIGNAL ;
    SHAPE ABUTMENT ;
    PORT
      LAYER M3_m ;
      RECT 0 60.795 0.07 60.865 ;
    END
  END rw0_rd_out[41]
  PIN rw0_rd_out[42]
    DIRECTION OUTPUT ;
    USE SIGNAL ;
    SHAPE ABUTMENT ;
    PORT
      LAYER M3_m ;
      RECT 0 61.075 0.07 61.145 ;
    END
  END rw0_rd_out[42]
  PIN rw0_rd_out[43]
    DIRECTION OUTPUT ;
    USE SIGNAL ;
    SHAPE ABUTMENT ;
    PORT
      LAYER M3_m ;
      RECT 0 61.355 0.07 61.425 ;
    END
  END rw0_rd_out[43]
  PIN rw0_rd_out[44]
    DIRECTION OUTPUT ;
    USE SIGNAL ;
    SHAPE ABUTMENT ;
    PORT
      LAYER M3_m ;
      RECT 0 61.635 0.07 61.705 ;
    END
  END rw0_rd_out[44]
  PIN rw0_rd_out[45]
    DIRECTION OUTPUT ;
    USE SIGNAL ;
    SHAPE ABUTMENT ;
    PORT
      LAYER M3_m ;
      RECT 0 61.915 0.07 61.985 ;
    END
  END rw0_rd_out[45]
  PIN rw0_rd_out[46]
    DIRECTION OUTPUT ;
    USE SIGNAL ;
    SHAPE ABUTMENT ;
    PORT
      LAYER M3_m ;
      RECT 0 62.195 0.07 62.265 ;
    END
  END rw0_rd_out[46]
  PIN rw0_rd_out[47]
    DIRECTION OUTPUT ;
    USE SIGNAL ;
    SHAPE ABUTMENT ;
    PORT
      LAYER M3_m ;
      RECT 0 62.475 0.07 62.545 ;
    END
  END rw0_rd_out[47]
  PIN rw0_rd_out[48]
    DIRECTION OUTPUT ;
    USE SIGNAL ;
    SHAPE ABUTMENT ;
    PORT
      LAYER M3_m ;
      RECT 0 62.755 0.07 62.825 ;
    END
  END rw0_rd_out[48]
  PIN rw0_rd_out[49]
    DIRECTION OUTPUT ;
    USE SIGNAL ;
    SHAPE ABUTMENT ;
    PORT
      LAYER M3_m ;
      RECT 0 63.035 0.07 63.105 ;
    END
  END rw0_rd_out[49]
  PIN rw0_rd_out[50]
    DIRECTION OUTPUT ;
    USE SIGNAL ;
    SHAPE ABUTMENT ;
    PORT
      LAYER M3_m ;
      RECT 0 63.315 0.07 63.385 ;
    END
  END rw0_rd_out[50]
  PIN rw0_rd_out[51]
    DIRECTION OUTPUT ;
    USE SIGNAL ;
    SHAPE ABUTMENT ;
    PORT
      LAYER M3_m ;
      RECT 0 63.595 0.07 63.665 ;
    END
  END rw0_rd_out[51]
  PIN rw0_rd_out[52]
    DIRECTION OUTPUT ;
    USE SIGNAL ;
    SHAPE ABUTMENT ;
    PORT
      LAYER M3_m ;
      RECT 0 63.875 0.07 63.945 ;
    END
  END rw0_rd_out[52]
  PIN rw0_rd_out[53]
    DIRECTION OUTPUT ;
    USE SIGNAL ;
    SHAPE ABUTMENT ;
    PORT
      LAYER M3_m ;
      RECT 0 64.155 0.07 64.225 ;
    END
  END rw0_rd_out[53]
  PIN rw0_rd_out[54]
    DIRECTION OUTPUT ;
    USE SIGNAL ;
    SHAPE ABUTMENT ;
    PORT
      LAYER M3_m ;
      RECT 0 64.435 0.07 64.505 ;
    END
  END rw0_rd_out[54]
  PIN rw0_rd_out[55]
    DIRECTION OUTPUT ;
    USE SIGNAL ;
    SHAPE ABUTMENT ;
    PORT
      LAYER M3_m ;
      RECT 0 64.715 0.07 64.785 ;
    END
  END rw0_rd_out[55]
  PIN rw0_rd_out[56]
    DIRECTION OUTPUT ;
    USE SIGNAL ;
    SHAPE ABUTMENT ;
    PORT
      LAYER M3_m ;
      RECT 0 64.995 0.07 65.065 ;
    END
  END rw0_rd_out[56]
  PIN rw0_rd_out[57]
    DIRECTION OUTPUT ;
    USE SIGNAL ;
    SHAPE ABUTMENT ;
    PORT
      LAYER M3_m ;
      RECT 0 65.275 0.07 65.345 ;
    END
  END rw0_rd_out[57]
  PIN rw0_rd_out[58]
    DIRECTION OUTPUT ;
    USE SIGNAL ;
    SHAPE ABUTMENT ;
    PORT
      LAYER M3_m ;
      RECT 0 65.555 0.07 65.625 ;
    END
  END rw0_rd_out[58]
  PIN rw0_rd_out[59]
    DIRECTION OUTPUT ;
    USE SIGNAL ;
    SHAPE ABUTMENT ;
    PORT
      LAYER M3_m ;
      RECT 0 65.835 0.07 65.905 ;
    END
  END rw0_rd_out[59]
  PIN rw0_rd_out[60]
    DIRECTION OUTPUT ;
    USE SIGNAL ;
    SHAPE ABUTMENT ;
    PORT
      LAYER M3_m ;
      RECT 0 66.115 0.07 66.185 ;
    END
  END rw0_rd_out[60]
  PIN rw0_rd_out[61]
    DIRECTION OUTPUT ;
    USE SIGNAL ;
    SHAPE ABUTMENT ;
    PORT
      LAYER M3_m ;
      RECT 0 66.395 0.07 66.465 ;
    END
  END rw0_rd_out[61]
  PIN rw0_rd_out[62]
    DIRECTION OUTPUT ;
    USE SIGNAL ;
    SHAPE ABUTMENT ;
    PORT
      LAYER M3_m ;
      RECT 0 66.675 0.07 66.745 ;
    END
  END rw0_rd_out[62]
  PIN rw0_rd_out[63]
    DIRECTION OUTPUT ;
    USE SIGNAL ;
    SHAPE ABUTMENT ;
    PORT
      LAYER M3_m ;
      RECT 0 66.955 0.07 67.025 ;
    END
  END rw0_rd_out[63]
  PIN rw0_rd_out[64]
    DIRECTION OUTPUT ;
    USE SIGNAL ;
    SHAPE ABUTMENT ;
    PORT
      LAYER M3_m ;
      RECT 0 67.235 0.07 67.305 ;
    END
  END rw0_rd_out[64]
  PIN rw0_rd_out[65]
    DIRECTION OUTPUT ;
    USE SIGNAL ;
    SHAPE ABUTMENT ;
    PORT
      LAYER M3_m ;
      RECT 0 67.515 0.07 67.585 ;
    END
  END rw0_rd_out[65]
  PIN rw0_rd_out[66]
    DIRECTION OUTPUT ;
    USE SIGNAL ;
    SHAPE ABUTMENT ;
    PORT
      LAYER M3_m ;
      RECT 0 67.795 0.07 67.865 ;
    END
  END rw0_rd_out[66]
  PIN rw0_rd_out[67]
    DIRECTION OUTPUT ;
    USE SIGNAL ;
    SHAPE ABUTMENT ;
    PORT
      LAYER M3_m ;
      RECT 0 68.075 0.07 68.145 ;
    END
  END rw0_rd_out[67]
  PIN rw0_rd_out[68]
    DIRECTION OUTPUT ;
    USE SIGNAL ;
    SHAPE ABUTMENT ;
    PORT
      LAYER M3_m ;
      RECT 0 68.355 0.07 68.425 ;
    END
  END rw0_rd_out[68]
  PIN rw0_rd_out[69]
    DIRECTION OUTPUT ;
    USE SIGNAL ;
    SHAPE ABUTMENT ;
    PORT
      LAYER M3_m ;
      RECT 0 68.635 0.07 68.705 ;
    END
  END rw0_rd_out[69]
  PIN rw0_rd_out[70]
    DIRECTION OUTPUT ;
    USE SIGNAL ;
    SHAPE ABUTMENT ;
    PORT
      LAYER M3_m ;
      RECT 0 68.915 0.07 68.985 ;
    END
  END rw0_rd_out[70]
  PIN rw0_rd_out[71]
    DIRECTION OUTPUT ;
    USE SIGNAL ;
    SHAPE ABUTMENT ;
    PORT
      LAYER M3_m ;
      RECT 0 69.195 0.07 69.265 ;
    END
  END rw0_rd_out[71]
  PIN rw0_rd_out[72]
    DIRECTION OUTPUT ;
    USE SIGNAL ;
    SHAPE ABUTMENT ;
    PORT
      LAYER M3_m ;
      RECT 0 69.475 0.07 69.545 ;
    END
  END rw0_rd_out[72]
  PIN rw0_rd_out[73]
    DIRECTION OUTPUT ;
    USE SIGNAL ;
    SHAPE ABUTMENT ;
    PORT
      LAYER M3_m ;
      RECT 0 69.755 0.07 69.825 ;
    END
  END rw0_rd_out[73]
  PIN rw0_rd_out[74]
    DIRECTION OUTPUT ;
    USE SIGNAL ;
    SHAPE ABUTMENT ;
    PORT
      LAYER M3_m ;
      RECT 0 70.035 0.07 70.105 ;
    END
  END rw0_rd_out[74]
  PIN rw0_rd_out[75]
    DIRECTION OUTPUT ;
    USE SIGNAL ;
    SHAPE ABUTMENT ;
    PORT
      LAYER M3_m ;
      RECT 0 70.315 0.07 70.385 ;
    END
  END rw0_rd_out[75]
  PIN rw0_rd_out[76]
    DIRECTION OUTPUT ;
    USE SIGNAL ;
    SHAPE ABUTMENT ;
    PORT
      LAYER M3_m ;
      RECT 0 70.595 0.07 70.665 ;
    END
  END rw0_rd_out[76]
  PIN rw0_rd_out[77]
    DIRECTION OUTPUT ;
    USE SIGNAL ;
    SHAPE ABUTMENT ;
    PORT
      LAYER M3_m ;
      RECT 0 70.875 0.07 70.945 ;
    END
  END rw0_rd_out[77]
  PIN rw0_rd_out[78]
    DIRECTION OUTPUT ;
    USE SIGNAL ;
    SHAPE ABUTMENT ;
    PORT
      LAYER M3_m ;
      RECT 0 71.155 0.07 71.225 ;
    END
  END rw0_rd_out[78]
  PIN rw0_rd_out[79]
    DIRECTION OUTPUT ;
    USE SIGNAL ;
    SHAPE ABUTMENT ;
    PORT
      LAYER M3_m ;
      RECT 0 71.435 0.07 71.505 ;
    END
  END rw0_rd_out[79]
  PIN rw0_rd_out[80]
    DIRECTION OUTPUT ;
    USE SIGNAL ;
    SHAPE ABUTMENT ;
    PORT
      LAYER M3_m ;
      RECT 0 71.715 0.07 71.785 ;
    END
  END rw0_rd_out[80]
  PIN rw0_rd_out[81]
    DIRECTION OUTPUT ;
    USE SIGNAL ;
    SHAPE ABUTMENT ;
    PORT
      LAYER M3_m ;
      RECT 0 71.995 0.07 72.065 ;
    END
  END rw0_rd_out[81]
  PIN rw0_rd_out[82]
    DIRECTION OUTPUT ;
    USE SIGNAL ;
    SHAPE ABUTMENT ;
    PORT
      LAYER M3_m ;
      RECT 0 72.275 0.07 72.345 ;
    END
  END rw0_rd_out[82]
  PIN rw0_rd_out[83]
    DIRECTION OUTPUT ;
    USE SIGNAL ;
    SHAPE ABUTMENT ;
    PORT
      LAYER M3_m ;
      RECT 0 72.555 0.07 72.625 ;
    END
  END rw0_rd_out[83]
  PIN rw0_rd_out[84]
    DIRECTION OUTPUT ;
    USE SIGNAL ;
    SHAPE ABUTMENT ;
    PORT
      LAYER M3_m ;
      RECT 0 72.835 0.07 72.905 ;
    END
  END rw0_rd_out[84]
  PIN rw0_rd_out[85]
    DIRECTION OUTPUT ;
    USE SIGNAL ;
    SHAPE ABUTMENT ;
    PORT
      LAYER M3_m ;
      RECT 0 73.115 0.07 73.185 ;
    END
  END rw0_rd_out[85]
  PIN rw0_rd_out[86]
    DIRECTION OUTPUT ;
    USE SIGNAL ;
    SHAPE ABUTMENT ;
    PORT
      LAYER M3_m ;
      RECT 0 73.395 0.07 73.465 ;
    END
  END rw0_rd_out[86]
  PIN rw0_rd_out[87]
    DIRECTION OUTPUT ;
    USE SIGNAL ;
    SHAPE ABUTMENT ;
    PORT
      LAYER M3_m ;
      RECT 0 73.675 0.07 73.745 ;
    END
  END rw0_rd_out[87]
  PIN rw0_rd_out[88]
    DIRECTION OUTPUT ;
    USE SIGNAL ;
    SHAPE ABUTMENT ;
    PORT
      LAYER M3_m ;
      RECT 0 73.955 0.07 74.025 ;
    END
  END rw0_rd_out[88]
  PIN rw0_rd_out[89]
    DIRECTION OUTPUT ;
    USE SIGNAL ;
    SHAPE ABUTMENT ;
    PORT
      LAYER M3_m ;
      RECT 0 74.235 0.07 74.305 ;
    END
  END rw0_rd_out[89]
  PIN rw0_rd_out[90]
    DIRECTION OUTPUT ;
    USE SIGNAL ;
    SHAPE ABUTMENT ;
    PORT
      LAYER M3_m ;
      RECT 0 74.515 0.07 74.585 ;
    END
  END rw0_rd_out[90]
  PIN rw0_rd_out[91]
    DIRECTION OUTPUT ;
    USE SIGNAL ;
    SHAPE ABUTMENT ;
    PORT
      LAYER M3_m ;
      RECT 0 74.795 0.07 74.865 ;
    END
  END rw0_rd_out[91]
  PIN rw0_rd_out[92]
    DIRECTION OUTPUT ;
    USE SIGNAL ;
    SHAPE ABUTMENT ;
    PORT
      LAYER M3_m ;
      RECT 0 75.075 0.07 75.145 ;
    END
  END rw0_rd_out[92]
  PIN rw0_rd_out[93]
    DIRECTION OUTPUT ;
    USE SIGNAL ;
    SHAPE ABUTMENT ;
    PORT
      LAYER M3_m ;
      RECT 0 75.355 0.07 75.425 ;
    END
  END rw0_rd_out[93]
  PIN rw0_rd_out[94]
    DIRECTION OUTPUT ;
    USE SIGNAL ;
    SHAPE ABUTMENT ;
    PORT
      LAYER M3_m ;
      RECT 0 75.635 0.07 75.705 ;
    END
  END rw0_rd_out[94]
  PIN rw0_rd_out[95]
    DIRECTION OUTPUT ;
    USE SIGNAL ;
    SHAPE ABUTMENT ;
    PORT
      LAYER M3_m ;
      RECT 0 75.915 0.07 75.985 ;
    END
  END rw0_rd_out[95]
  PIN rw0_rd_out[96]
    DIRECTION OUTPUT ;
    USE SIGNAL ;
    SHAPE ABUTMENT ;
    PORT
      LAYER M3_m ;
      RECT 0 76.195 0.07 76.265 ;
    END
  END rw0_rd_out[96]
  PIN rw0_rd_out[97]
    DIRECTION OUTPUT ;
    USE SIGNAL ;
    SHAPE ABUTMENT ;
    PORT
      LAYER M3_m ;
      RECT 0 76.475 0.07 76.545 ;
    END
  END rw0_rd_out[97]
  PIN rw0_rd_out[98]
    DIRECTION OUTPUT ;
    USE SIGNAL ;
    SHAPE ABUTMENT ;
    PORT
      LAYER M3_m ;
      RECT 0 76.755 0.07 76.825 ;
    END
  END rw0_rd_out[98]
  PIN rw0_rd_out[99]
    DIRECTION OUTPUT ;
    USE SIGNAL ;
    SHAPE ABUTMENT ;
    PORT
      LAYER M3_m ;
      RECT 0 77.035 0.07 77.105 ;
    END
  END rw0_rd_out[99]
  PIN rw0_rd_out[100]
    DIRECTION OUTPUT ;
    USE SIGNAL ;
    SHAPE ABUTMENT ;
    PORT
      LAYER M3_m ;
      RECT 0 77.315 0.07 77.385 ;
    END
  END rw0_rd_out[100]
  PIN rw0_rd_out[101]
    DIRECTION OUTPUT ;
    USE SIGNAL ;
    SHAPE ABUTMENT ;
    PORT
      LAYER M3_m ;
      RECT 0 77.595 0.07 77.665 ;
    END
  END rw0_rd_out[101]
  PIN rw0_rd_out[102]
    DIRECTION OUTPUT ;
    USE SIGNAL ;
    SHAPE ABUTMENT ;
    PORT
      LAYER M3_m ;
      RECT 0 77.875 0.07 77.945 ;
    END
  END rw0_rd_out[102]
  PIN rw0_rd_out[103]
    DIRECTION OUTPUT ;
    USE SIGNAL ;
    SHAPE ABUTMENT ;
    PORT
      LAYER M3_m ;
      RECT 0 78.155 0.07 78.225 ;
    END
  END rw0_rd_out[103]
  PIN rw0_rd_out[104]
    DIRECTION OUTPUT ;
    USE SIGNAL ;
    SHAPE ABUTMENT ;
    PORT
      LAYER M3_m ;
      RECT 0 78.435 0.07 78.505 ;
    END
  END rw0_rd_out[104]
  PIN rw0_rd_out[105]
    DIRECTION OUTPUT ;
    USE SIGNAL ;
    SHAPE ABUTMENT ;
    PORT
      LAYER M3_m ;
      RECT 0 78.715 0.07 78.785 ;
    END
  END rw0_rd_out[105]
  PIN rw0_rd_out[106]
    DIRECTION OUTPUT ;
    USE SIGNAL ;
    SHAPE ABUTMENT ;
    PORT
      LAYER M3_m ;
      RECT 0 78.995 0.07 79.065 ;
    END
  END rw0_rd_out[106]
  PIN rw0_rd_out[107]
    DIRECTION OUTPUT ;
    USE SIGNAL ;
    SHAPE ABUTMENT ;
    PORT
      LAYER M3_m ;
      RECT 0 79.275 0.07 79.345 ;
    END
  END rw0_rd_out[107]
  PIN rw0_rd_out[108]
    DIRECTION OUTPUT ;
    USE SIGNAL ;
    SHAPE ABUTMENT ;
    PORT
      LAYER M3_m ;
      RECT 0 79.555 0.07 79.625 ;
    END
  END rw0_rd_out[108]
  PIN rw0_rd_out[109]
    DIRECTION OUTPUT ;
    USE SIGNAL ;
    SHAPE ABUTMENT ;
    PORT
      LAYER M3_m ;
      RECT 0 79.835 0.07 79.905 ;
    END
  END rw0_rd_out[109]
  PIN rw0_rd_out[110]
    DIRECTION OUTPUT ;
    USE SIGNAL ;
    SHAPE ABUTMENT ;
    PORT
      LAYER M3_m ;
      RECT 0 80.115 0.07 80.185 ;
    END
  END rw0_rd_out[110]
  PIN rw0_rd_out[111]
    DIRECTION OUTPUT ;
    USE SIGNAL ;
    SHAPE ABUTMENT ;
    PORT
      LAYER M3_m ;
      RECT 0 80.395 0.07 80.465 ;
    END
  END rw0_rd_out[111]
  PIN rw0_rd_out[112]
    DIRECTION OUTPUT ;
    USE SIGNAL ;
    SHAPE ABUTMENT ;
    PORT
      LAYER M3_m ;
      RECT 0 80.675 0.07 80.745 ;
    END
  END rw0_rd_out[112]
  PIN rw0_rd_out[113]
    DIRECTION OUTPUT ;
    USE SIGNAL ;
    SHAPE ABUTMENT ;
    PORT
      LAYER M3_m ;
      RECT 0 80.955 0.07 81.025 ;
    END
  END rw0_rd_out[113]
  PIN rw0_rd_out[114]
    DIRECTION OUTPUT ;
    USE SIGNAL ;
    SHAPE ABUTMENT ;
    PORT
      LAYER M3_m ;
      RECT 0 81.235 0.07 81.305 ;
    END
  END rw0_rd_out[114]
  PIN rw0_rd_out[115]
    DIRECTION OUTPUT ;
    USE SIGNAL ;
    SHAPE ABUTMENT ;
    PORT
      LAYER M3_m ;
      RECT 0 81.515 0.07 81.585 ;
    END
  END rw0_rd_out[115]
  PIN rw0_rd_out[116]
    DIRECTION OUTPUT ;
    USE SIGNAL ;
    SHAPE ABUTMENT ;
    PORT
      LAYER M3_m ;
      RECT 0 81.795 0.07 81.865 ;
    END
  END rw0_rd_out[116]
  PIN rw0_rd_out[117]
    DIRECTION OUTPUT ;
    USE SIGNAL ;
    SHAPE ABUTMENT ;
    PORT
      LAYER M3_m ;
      RECT 0 82.075 0.07 82.145 ;
    END
  END rw0_rd_out[117]
  PIN rw0_rd_out[118]
    DIRECTION OUTPUT ;
    USE SIGNAL ;
    SHAPE ABUTMENT ;
    PORT
      LAYER M3_m ;
      RECT 0 82.355 0.07 82.425 ;
    END
  END rw0_rd_out[118]
  PIN rw0_rd_out[119]
    DIRECTION OUTPUT ;
    USE SIGNAL ;
    SHAPE ABUTMENT ;
    PORT
      LAYER M3_m ;
      RECT 0 82.635 0.07 82.705 ;
    END
  END rw0_rd_out[119]
  PIN rw0_rd_out[120]
    DIRECTION OUTPUT ;
    USE SIGNAL ;
    SHAPE ABUTMENT ;
    PORT
      LAYER M3_m ;
      RECT 0 82.915 0.07 82.985 ;
    END
  END rw0_rd_out[120]
  PIN rw0_rd_out[121]
    DIRECTION OUTPUT ;
    USE SIGNAL ;
    SHAPE ABUTMENT ;
    PORT
      LAYER M3_m ;
      RECT 0 83.195 0.07 83.265 ;
    END
  END rw0_rd_out[121]
  PIN rw0_rd_out[122]
    DIRECTION OUTPUT ;
    USE SIGNAL ;
    SHAPE ABUTMENT ;
    PORT
      LAYER M3_m ;
      RECT 0 83.475 0.07 83.545 ;
    END
  END rw0_rd_out[122]
  PIN rw0_rd_out[123]
    DIRECTION OUTPUT ;
    USE SIGNAL ;
    SHAPE ABUTMENT ;
    PORT
      LAYER M3_m ;
      RECT 0 83.755 0.07 83.825 ;
    END
  END rw0_rd_out[123]
  PIN rw0_rd_out[124]
    DIRECTION OUTPUT ;
    USE SIGNAL ;
    SHAPE ABUTMENT ;
    PORT
      LAYER M3_m ;
      RECT 0 84.035 0.07 84.105 ;
    END
  END rw0_rd_out[124]
  PIN rw0_rd_out[125]
    DIRECTION OUTPUT ;
    USE SIGNAL ;
    SHAPE ABUTMENT ;
    PORT
      LAYER M3_m ;
      RECT 0 84.315 0.07 84.385 ;
    END
  END rw0_rd_out[125]
  PIN rw0_rd_out[126]
    DIRECTION OUTPUT ;
    USE SIGNAL ;
    SHAPE ABUTMENT ;
    PORT
      LAYER M3_m ;
      RECT 0 84.595 0.07 84.665 ;
    END
  END rw0_rd_out[126]
  PIN rw0_rd_out[127]
    DIRECTION OUTPUT ;
    USE SIGNAL ;
    SHAPE ABUTMENT ;
    PORT
      LAYER M3_m ;
      RECT 0 84.875 0.07 84.945 ;
    END
  END rw0_rd_out[127]
  PIN rw0_rd_out[128]
    DIRECTION OUTPUT ;
    USE SIGNAL ;
    SHAPE ABUTMENT ;
    PORT
      LAYER M3_m ;
      RECT 0 85.155 0.07 85.225 ;
    END
  END rw0_rd_out[128]
  PIN rw0_rd_out[129]
    DIRECTION OUTPUT ;
    USE SIGNAL ;
    SHAPE ABUTMENT ;
    PORT
      LAYER M3_m ;
      RECT 0 85.435 0.07 85.505 ;
    END
  END rw0_rd_out[129]
  PIN rw0_rd_out[130]
    DIRECTION OUTPUT ;
    USE SIGNAL ;
    SHAPE ABUTMENT ;
    PORT
      LAYER M3_m ;
      RECT 0 85.715 0.07 85.785 ;
    END
  END rw0_rd_out[130]
  PIN rw0_rd_out[131]
    DIRECTION OUTPUT ;
    USE SIGNAL ;
    SHAPE ABUTMENT ;
    PORT
      LAYER M3_m ;
      RECT 0 85.995 0.07 86.065 ;
    END
  END rw0_rd_out[131]
  PIN rw0_rd_out[132]
    DIRECTION OUTPUT ;
    USE SIGNAL ;
    SHAPE ABUTMENT ;
    PORT
      LAYER M3_m ;
      RECT 0 86.275 0.07 86.345 ;
    END
  END rw0_rd_out[132]
  PIN rw0_rd_out[133]
    DIRECTION OUTPUT ;
    USE SIGNAL ;
    SHAPE ABUTMENT ;
    PORT
      LAYER M3_m ;
      RECT 0 86.555 0.07 86.625 ;
    END
  END rw0_rd_out[133]
  PIN rw0_rd_out[134]
    DIRECTION OUTPUT ;
    USE SIGNAL ;
    SHAPE ABUTMENT ;
    PORT
      LAYER M3_m ;
      RECT 0 86.835 0.07 86.905 ;
    END
  END rw0_rd_out[134]
  PIN rw0_rd_out[135]
    DIRECTION OUTPUT ;
    USE SIGNAL ;
    SHAPE ABUTMENT ;
    PORT
      LAYER M3_m ;
      RECT 0 87.115 0.07 87.185 ;
    END
  END rw0_rd_out[135]
  PIN rw0_rd_out[136]
    DIRECTION OUTPUT ;
    USE SIGNAL ;
    SHAPE ABUTMENT ;
    PORT
      LAYER M3_m ;
      RECT 0 87.395 0.07 87.465 ;
    END
  END rw0_rd_out[136]
  PIN rw0_rd_out[137]
    DIRECTION OUTPUT ;
    USE SIGNAL ;
    SHAPE ABUTMENT ;
    PORT
      LAYER M3_m ;
      RECT 0 87.675 0.07 87.745 ;
    END
  END rw0_rd_out[137]
  PIN rw0_rd_out[138]
    DIRECTION OUTPUT ;
    USE SIGNAL ;
    SHAPE ABUTMENT ;
    PORT
      LAYER M3_m ;
      RECT 0 87.955 0.07 88.025 ;
    END
  END rw0_rd_out[138]
  PIN rw0_rd_out[139]
    DIRECTION OUTPUT ;
    USE SIGNAL ;
    SHAPE ABUTMENT ;
    PORT
      LAYER M3_m ;
      RECT 0 88.235 0.07 88.305 ;
    END
  END rw0_rd_out[139]
  PIN rw0_rd_out[140]
    DIRECTION OUTPUT ;
    USE SIGNAL ;
    SHAPE ABUTMENT ;
    PORT
      LAYER M3_m ;
      RECT 0 88.515 0.07 88.585 ;
    END
  END rw0_rd_out[140]
  PIN rw0_rd_out[141]
    DIRECTION OUTPUT ;
    USE SIGNAL ;
    SHAPE ABUTMENT ;
    PORT
      LAYER M3_m ;
      RECT 0 88.795 0.07 88.865 ;
    END
  END rw0_rd_out[141]
  PIN rw0_rd_out[142]
    DIRECTION OUTPUT ;
    USE SIGNAL ;
    SHAPE ABUTMENT ;
    PORT
      LAYER M3_m ;
      RECT 0 89.075 0.07 89.145 ;
    END
  END rw0_rd_out[142]
  PIN rw0_rd_out[143]
    DIRECTION OUTPUT ;
    USE SIGNAL ;
    SHAPE ABUTMENT ;
    PORT
      LAYER M3_m ;
      RECT 0 89.355 0.07 89.425 ;
    END
  END rw0_rd_out[143]
  PIN rw0_rd_out[144]
    DIRECTION OUTPUT ;
    USE SIGNAL ;
    SHAPE ABUTMENT ;
    PORT
      LAYER M3_m ;
      RECT 0 89.635 0.07 89.705 ;
    END
  END rw0_rd_out[144]
  PIN rw0_rd_out[145]
    DIRECTION OUTPUT ;
    USE SIGNAL ;
    SHAPE ABUTMENT ;
    PORT
      LAYER M3_m ;
      RECT 0 89.915 0.07 89.985 ;
    END
  END rw0_rd_out[145]
  PIN rw0_rd_out[146]
    DIRECTION OUTPUT ;
    USE SIGNAL ;
    SHAPE ABUTMENT ;
    PORT
      LAYER M3_m ;
      RECT 0 90.195 0.07 90.265 ;
    END
  END rw0_rd_out[146]
  PIN rw0_rd_out[147]
    DIRECTION OUTPUT ;
    USE SIGNAL ;
    SHAPE ABUTMENT ;
    PORT
      LAYER M3_m ;
      RECT 0 90.475 0.07 90.545 ;
    END
  END rw0_rd_out[147]
  PIN rw0_rd_out[148]
    DIRECTION OUTPUT ;
    USE SIGNAL ;
    SHAPE ABUTMENT ;
    PORT
      LAYER M3_m ;
      RECT 0 90.755 0.07 90.825 ;
    END
  END rw0_rd_out[148]
  PIN rw0_rd_out[149]
    DIRECTION OUTPUT ;
    USE SIGNAL ;
    SHAPE ABUTMENT ;
    PORT
      LAYER M3_m ;
      RECT 0 91.035 0.07 91.105 ;
    END
  END rw0_rd_out[149]
  PIN rw0_rd_out[150]
    DIRECTION OUTPUT ;
    USE SIGNAL ;
    SHAPE ABUTMENT ;
    PORT
      LAYER M3_m ;
      RECT 0 91.315 0.07 91.385 ;
    END
  END rw0_rd_out[150]
  PIN rw0_rd_out[151]
    DIRECTION OUTPUT ;
    USE SIGNAL ;
    SHAPE ABUTMENT ;
    PORT
      LAYER M3_m ;
      RECT 0 91.595 0.07 91.665 ;
    END
  END rw0_rd_out[151]
  PIN rw0_rd_out[152]
    DIRECTION OUTPUT ;
    USE SIGNAL ;
    SHAPE ABUTMENT ;
    PORT
      LAYER M3_m ;
      RECT 0 91.875 0.07 91.945 ;
    END
  END rw0_rd_out[152]
  PIN rw0_rd_out[153]
    DIRECTION OUTPUT ;
    USE SIGNAL ;
    SHAPE ABUTMENT ;
    PORT
      LAYER M3_m ;
      RECT 0 92.155 0.07 92.225 ;
    END
  END rw0_rd_out[153]
  PIN rw0_rd_out[154]
    DIRECTION OUTPUT ;
    USE SIGNAL ;
    SHAPE ABUTMENT ;
    PORT
      LAYER M3_m ;
      RECT 0 92.435 0.07 92.505 ;
    END
  END rw0_rd_out[154]
  PIN rw0_rd_out[155]
    DIRECTION OUTPUT ;
    USE SIGNAL ;
    SHAPE ABUTMENT ;
    PORT
      LAYER M3_m ;
      RECT 0 92.715 0.07 92.785 ;
    END
  END rw0_rd_out[155]
  PIN rw0_rd_out[156]
    DIRECTION OUTPUT ;
    USE SIGNAL ;
    SHAPE ABUTMENT ;
    PORT
      LAYER M3_m ;
      RECT 0 92.995 0.07 93.065 ;
    END
  END rw0_rd_out[156]
  PIN rw0_rd_out[157]
    DIRECTION OUTPUT ;
    USE SIGNAL ;
    SHAPE ABUTMENT ;
    PORT
      LAYER M3_m ;
      RECT 0 93.275 0.07 93.345 ;
    END
  END rw0_rd_out[157]
  PIN rw0_rd_out[158]
    DIRECTION OUTPUT ;
    USE SIGNAL ;
    SHAPE ABUTMENT ;
    PORT
      LAYER M3_m ;
      RECT 0 93.555 0.07 93.625 ;
    END
  END rw0_rd_out[158]
  PIN rw0_rd_out[159]
    DIRECTION OUTPUT ;
    USE SIGNAL ;
    SHAPE ABUTMENT ;
    PORT
      LAYER M3_m ;
      RECT 0 93.835 0.07 93.905 ;
    END
  END rw0_rd_out[159]
  PIN rw0_rd_out[160]
    DIRECTION OUTPUT ;
    USE SIGNAL ;
    SHAPE ABUTMENT ;
    PORT
      LAYER M3_m ;
      RECT 0 94.115 0.07 94.185 ;
    END
  END rw0_rd_out[160]
  PIN rw0_rd_out[161]
    DIRECTION OUTPUT ;
    USE SIGNAL ;
    SHAPE ABUTMENT ;
    PORT
      LAYER M3_m ;
      RECT 0 94.395 0.07 94.465 ;
    END
  END rw0_rd_out[161]
  PIN rw0_rd_out[162]
    DIRECTION OUTPUT ;
    USE SIGNAL ;
    SHAPE ABUTMENT ;
    PORT
      LAYER M3_m ;
      RECT 0 94.675 0.07 94.745 ;
    END
  END rw0_rd_out[162]
  PIN rw0_rd_out[163]
    DIRECTION OUTPUT ;
    USE SIGNAL ;
    SHAPE ABUTMENT ;
    PORT
      LAYER M3_m ;
      RECT 0 94.955 0.07 95.025 ;
    END
  END rw0_rd_out[163]
  PIN rw0_rd_out[164]
    DIRECTION OUTPUT ;
    USE SIGNAL ;
    SHAPE ABUTMENT ;
    PORT
      LAYER M3_m ;
      RECT 0 95.235 0.07 95.305 ;
    END
  END rw0_rd_out[164]
  PIN rw0_rd_out[165]
    DIRECTION OUTPUT ;
    USE SIGNAL ;
    SHAPE ABUTMENT ;
    PORT
      LAYER M3_m ;
      RECT 0 95.515 0.07 95.585 ;
    END
  END rw0_rd_out[165]
  PIN rw0_rd_out[166]
    DIRECTION OUTPUT ;
    USE SIGNAL ;
    SHAPE ABUTMENT ;
    PORT
      LAYER M3_m ;
      RECT 0 95.795 0.07 95.865 ;
    END
  END rw0_rd_out[166]
  PIN rw0_rd_out[167]
    DIRECTION OUTPUT ;
    USE SIGNAL ;
    SHAPE ABUTMENT ;
    PORT
      LAYER M3_m ;
      RECT 0 96.075 0.07 96.145 ;
    END
  END rw0_rd_out[167]
  PIN rw0_addr_in[0]
    DIRECTION INPUT ;
    USE SIGNAL ;
    SHAPE ABUTMENT ;
    PORT
      LAYER M3_m ;
      RECT 0 96.355 0.07 96.425 ;
    END
  END rw0_addr_in[0]
  PIN rw0_addr_in[1]
    DIRECTION INPUT ;
    USE SIGNAL ;
    SHAPE ABUTMENT ;
    PORT
      LAYER M3_m ;
      RECT 0 96.635 0.07 96.705 ;
    END
  END rw0_addr_in[1]
  PIN rw0_addr_in[2]
    DIRECTION INPUT ;
    USE SIGNAL ;
    SHAPE ABUTMENT ;
    PORT
      LAYER M3_m ;
      RECT 0 96.915 0.07 96.985 ;
    END
  END rw0_addr_in[2]
  PIN rw0_addr_in[3]
    DIRECTION INPUT ;
    USE SIGNAL ;
    SHAPE ABUTMENT ;
    PORT
      LAYER M3_m ;
      RECT 0 97.195 0.07 97.265 ;
    END
  END rw0_addr_in[3]
  PIN rw0_addr_in[4]
    DIRECTION INPUT ;
    USE SIGNAL ;
    SHAPE ABUTMENT ;
    PORT
      LAYER M3_m ;
      RECT 0 97.475 0.07 97.545 ;
    END
  END rw0_addr_in[4]
  PIN rw0_addr_in[5]
    DIRECTION INPUT ;
    USE SIGNAL ;
    SHAPE ABUTMENT ;
    PORT
      LAYER M3_m ;
      RECT 0 97.755 0.07 97.825 ;
    END
  END rw0_addr_in[5]
  PIN rw0_we_in
    DIRECTION INPUT ;
    USE SIGNAL ;
    SHAPE ABUTMENT ;
    PORT
      LAYER M3_m ;
      RECT 0 98.035 0.07 98.105 ;
    END
  END rw0_we_in
  PIN rw0_ce_in
    DIRECTION INPUT ;
    USE SIGNAL ;
    SHAPE ABUTMENT ;
    PORT
      LAYER M3_m ;
      RECT 0 98.315 0.07 98.385 ;
    END
  END rw0_ce_in
  PIN rw0_clk
    DIRECTION INPUT ;
    USE SIGNAL ;
    SHAPE ABUTMENT ;
    PORT
      LAYER M3_m ;
      RECT 0 98.595 0.07 98.665 ;
    END
  END rw0_clk
  PIN VSS
    DIRECTION INOUT ;
    USE GROUND ;
    PORT
      LAYER M4_m ;
      RECT 1 0.84 1.28 144.76 ;
      RECT 3.24 0.84 3.52 144.76 ;
      RECT 5.48 0.84 5.76 144.76 ;
      RECT 7.72 0.84 8 144.76 ;
      RECT 9.96 0.84 10.24 144.76 ;
      RECT 12.2 0.84 12.48 144.76 ;
      RECT 14.44 0.84 14.72 144.76 ;
      RECT 16.68 0.84 16.96 144.76 ;
      RECT 18.92 0.84 19.2 144.76 ;
      RECT 21.16 0.84 21.44 144.76 ;
      RECT 23.4 0.84 23.68 144.76 ;
      RECT 25.64 0.84 25.92 144.76 ;
      RECT 27.88 0.84 28.16 144.76 ;
      RECT 30.12 0.84 30.4 144.76 ;
      RECT 32.36 0.84 32.64 144.76 ;
      RECT 34.6 0.84 34.88 144.76 ;
      RECT 36.84 0.84 37.12 144.76 ;
      RECT 39.08 0.84 39.36 144.76 ;
      RECT 41.32 0.84 41.6 144.76 ;
      RECT 43.56 0.84 43.84 144.76 ;
      RECT 45.8 0.84 46.08 144.76 ;
      RECT 48.04 0.84 48.32 144.76 ;
      RECT 50.28 0.84 50.56 144.76 ;
      RECT 52.52 0.84 52.8 144.76 ;
      RECT 54.76 0.84 55.04 144.76 ;
      RECT 57 0.84 57.28 144.76 ;
      RECT 59.24 0.84 59.52 144.76 ;
      RECT 61.48 0.84 61.76 144.76 ;
      RECT 63.72 0.84 64 144.76 ;
      RECT 65.96 0.84 66.24 144.76 ;
      RECT 68.2 0.84 68.48 144.76 ;
      RECT 70.44 0.84 70.72 144.76 ;
      RECT 72.68 0.84 72.96 144.76 ;
      RECT 74.92 0.84 75.2 144.76 ;
      RECT 77.16 0.84 77.44 144.76 ;
      RECT 79.4 0.84 79.68 144.76 ;
      RECT 81.64 0.84 81.92 144.76 ;
      RECT 83.88 0.84 84.16 144.76 ;
      RECT 86.12 0.84 86.4 144.76 ;
      RECT 88.36 0.84 88.64 144.76 ;
    END
  END VSS
  PIN VDD
    DIRECTION INOUT ;
    USE POWER ;
    PORT
      LAYER M4_m ;
      RECT 2.12 0.84 2.4 144.76 ;
      RECT 4.36 0.84 4.64 144.76 ;
      RECT 6.6 0.84 6.88 144.76 ;
      RECT 8.84 0.84 9.12 144.76 ;
      RECT 11.08 0.84 11.36 144.76 ;
      RECT 13.32 0.84 13.6 144.76 ;
      RECT 15.56 0.84 15.84 144.76 ;
      RECT 17.8 0.84 18.08 144.76 ;
      RECT 20.04 0.84 20.32 144.76 ;
      RECT 22.28 0.84 22.56 144.76 ;
      RECT 24.52 0.84 24.8 144.76 ;
      RECT 26.76 0.84 27.04 144.76 ;
      RECT 29 0.84 29.28 144.76 ;
      RECT 31.24 0.84 31.52 144.76 ;
      RECT 33.48 0.84 33.76 144.76 ;
      RECT 35.72 0.84 36 144.76 ;
      RECT 37.96 0.84 38.24 144.76 ;
      RECT 40.2 0.84 40.48 144.76 ;
      RECT 42.44 0.84 42.72 144.76 ;
      RECT 44.68 0.84 44.96 144.76 ;
      RECT 46.92 0.84 47.2 144.76 ;
      RECT 49.16 0.84 49.44 144.76 ;
      RECT 51.4 0.84 51.68 144.76 ;
      RECT 53.64 0.84 53.92 144.76 ;
      RECT 55.88 0.84 56.16 144.76 ;
      RECT 58.12 0.84 58.4 144.76 ;
      RECT 60.36 0.84 60.64 144.76 ;
      RECT 62.6 0.84 62.88 144.76 ;
      RECT 64.84 0.84 65.12 144.76 ;
      RECT 67.08 0.84 67.36 144.76 ;
      RECT 69.32 0.84 69.6 144.76 ;
      RECT 71.56 0.84 71.84 144.76 ;
      RECT 73.8 0.84 74.08 144.76 ;
      RECT 76.04 0.84 76.32 144.76 ;
      RECT 78.28 0.84 78.56 144.76 ;
      RECT 80.52 0.84 80.8 144.76 ;
      RECT 82.76 0.84 83.04 144.76 ;
      RECT 85 0.84 85.28 144.76 ;
      RECT 87.24 0.84 87.52 144.76 ;
    END
  END VDD
  OBS
    LAYER M1_m ;
    RECT 0 0 89.3 145.6 ;
    LAYER M2_m ;
    RECT 0 0 89.3 145.6 ;
  END
END ht45_rocketgemmini_rockettile_icache_tag_array_ext_upper

END LIBRARY
